VERSION 5.7 ;
BUSBITCHARS "[]" ;
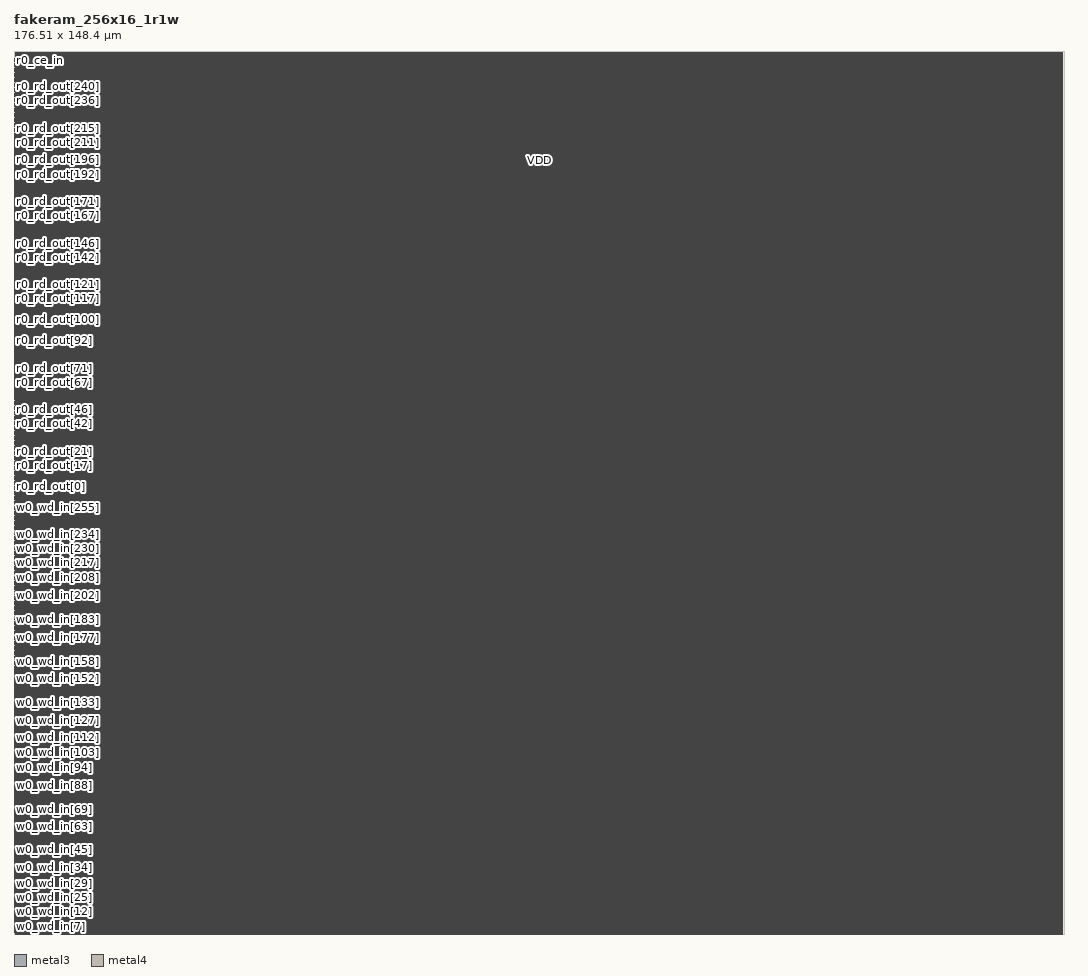
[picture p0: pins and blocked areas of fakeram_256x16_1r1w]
MACRO fakeram_256x16_1r1w
  FOREIGN fakeram_256x16_1r1w 0 0 ;
  SYMMETRY X Y R90 ;
  SIZE 176.510 BY 148.400 ;
  CLASS BLOCK ;
  PIN w0_wd_in[0]
    DIRECTION INPUT ;
    USE SIGNAL ;
    SHAPE ABUTMENT ;
    PORT
      LAYER metal3 ;
      RECT 0.000 0.280 0.140 0.420 ;
    END
  END w0_wd_in[0]
  PIN w0_wd_in[1]
    DIRECTION INPUT ;
    USE SIGNAL ;
    SHAPE ABUTMENT ;
    PORT
      LAYER metal3 ;
      RECT 0.000 0.560 0.140 0.700 ;
    END
  END w0_wd_in[1]
  PIN w0_wd_in[2]
    DIRECTION INPUT ;
    USE SIGNAL ;
    SHAPE ABUTMENT ;
    PORT
      LAYER metal3 ;
      RECT 0.000 0.840 0.140 0.980 ;
    END
  END w0_wd_in[2]
  PIN w0_wd_in[3]
    DIRECTION INPUT ;
    USE SIGNAL ;
    SHAPE ABUTMENT ;
    PORT
      LAYER metal3 ;
      RECT 0.000 1.120 0.140 1.260 ;
    END
  END w0_wd_in[3]
  PIN w0_wd_in[4]
    DIRECTION INPUT ;
    USE SIGNAL ;
    SHAPE ABUTMENT ;
    PORT
      LAYER metal3 ;
      RECT 0.000 1.400 0.140 1.540 ;
    END
  END w0_wd_in[4]
  PIN w0_wd_in[5]
    DIRECTION INPUT ;
    USE SIGNAL ;
    SHAPE ABUTMENT ;
    PORT
      LAYER metal3 ;
      RECT 0.000 1.680 0.140 1.820 ;
    END
  END w0_wd_in[5]
  PIN w0_wd_in[6]
    DIRECTION INPUT ;
    USE SIGNAL ;
    SHAPE ABUTMENT ;
    PORT
      LAYER metal3 ;
      RECT 0.000 1.960 0.140 2.100 ;
    END
  END w0_wd_in[6]
  PIN w0_wd_in[7]
    DIRECTION INPUT ;
    USE SIGNAL ;
    SHAPE ABUTMENT ;
    PORT
      LAYER metal3 ;
      RECT 0.000 2.240 0.140 2.380 ;
    END
  END w0_wd_in[7]
  PIN w0_wd_in[8]
    DIRECTION INPUT ;
    USE SIGNAL ;
    SHAPE ABUTMENT ;
    PORT
      LAYER metal3 ;
      RECT 0.000 2.520 0.140 2.660 ;
    END
  END w0_wd_in[8]
  PIN w0_wd_in[9]
    DIRECTION INPUT ;
    USE SIGNAL ;
    SHAPE ABUTMENT ;
    PORT
      LAYER metal3 ;
      RECT 0.000 2.800 0.140 2.940 ;
    END
  END w0_wd_in[9]
  PIN w0_wd_in[10]
    DIRECTION INPUT ;
    USE SIGNAL ;
    SHAPE ABUTMENT ;
    PORT
      LAYER metal3 ;
      RECT 0.000 3.080 0.140 3.220 ;
    END
  END w0_wd_in[10]
  PIN w0_wd_in[11]
    DIRECTION INPUT ;
    USE SIGNAL ;
    SHAPE ABUTMENT ;
    PORT
      LAYER metal3 ;
      RECT 0.000 3.360 0.140 3.500 ;
    END
  END w0_wd_in[11]
  PIN w0_wd_in[12]
    DIRECTION INPUT ;
    USE SIGNAL ;
    SHAPE ABUTMENT ;
    PORT
      LAYER metal3 ;
      RECT 0.000 3.640 0.140 3.780 ;
    END
  END w0_wd_in[12]
  PIN w0_wd_in[13]
    DIRECTION INPUT ;
    USE SIGNAL ;
    SHAPE ABUTMENT ;
    PORT
      LAYER metal3 ;
      RECT 0.000 3.920 0.140 4.060 ;
    END
  END w0_wd_in[13]
  PIN w0_wd_in[14]
    DIRECTION INPUT ;
    USE SIGNAL ;
    SHAPE ABUTMENT ;
    PORT
      LAYER metal3 ;
      RECT 0.000 4.200 0.140 4.340 ;
    END
  END w0_wd_in[14]
  PIN w0_wd_in[15]
    DIRECTION INPUT ;
    USE SIGNAL ;
    SHAPE ABUTMENT ;
    PORT
      LAYER metal3 ;
      RECT 0.000 4.480 0.140 4.620 ;
    END
  END w0_wd_in[15]
  PIN w0_wd_in[16]
    DIRECTION INPUT ;
    USE SIGNAL ;
    SHAPE ABUTMENT ;
    PORT
      LAYER metal3 ;
      RECT 0.000 4.760 0.140 4.900 ;
    END
  END w0_wd_in[16]
  PIN w0_wd_in[17]
    DIRECTION INPUT ;
    USE SIGNAL ;
    SHAPE ABUTMENT ;
    PORT
      LAYER metal3 ;
      RECT 0.000 5.040 0.140 5.180 ;
    END
  END w0_wd_in[17]
  PIN w0_wd_in[18]
    DIRECTION INPUT ;
    USE SIGNAL ;
    SHAPE ABUTMENT ;
    PORT
      LAYER metal3 ;
      RECT 0.000 5.320 0.140 5.460 ;
    END
  END w0_wd_in[18]
  PIN w0_wd_in[19]
    DIRECTION INPUT ;
    USE SIGNAL ;
    SHAPE ABUTMENT ;
    PORT
      LAYER metal3 ;
      RECT 0.000 5.600 0.140 5.740 ;
    END
  END w0_wd_in[19]
  PIN w0_wd_in[20]
    DIRECTION INPUT ;
    USE SIGNAL ;
    SHAPE ABUTMENT ;
    PORT
      LAYER metal3 ;
      RECT 0.000 5.880 0.140 6.020 ;
    END
  END w0_wd_in[20]
  PIN w0_wd_in[21]
    DIRECTION INPUT ;
    USE SIGNAL ;
    SHAPE ABUTMENT ;
    PORT
      LAYER metal3 ;
      RECT 0.000 6.160 0.140 6.300 ;
    END
  END w0_wd_in[21]
  PIN w0_wd_in[22]
    DIRECTION INPUT ;
    USE SIGNAL ;
    SHAPE ABUTMENT ;
    PORT
      LAYER metal3 ;
      RECT 0.000 6.440 0.140 6.580 ;
    END
  END w0_wd_in[22]
  PIN w0_wd_in[23]
    DIRECTION INPUT ;
    USE SIGNAL ;
    SHAPE ABUTMENT ;
    PORT
      LAYER metal3 ;
      RECT 0.000 6.720 0.140 6.860 ;
    END
  END w0_wd_in[23]
  PIN w0_wd_in[24]
    DIRECTION INPUT ;
    USE SIGNAL ;
    SHAPE ABUTMENT ;
    PORT
      LAYER metal3 ;
      RECT 0.000 7.000 0.140 7.140 ;
    END
  END w0_wd_in[24]
  PIN w0_wd_in[25]
    DIRECTION INPUT ;
    USE SIGNAL ;
    SHAPE ABUTMENT ;
    PORT
      LAYER metal3 ;
      RECT 0.000 7.280 0.140 7.420 ;
    END
  END w0_wd_in[25]
  PIN w0_wd_in[26]
    DIRECTION INPUT ;
    USE SIGNAL ;
    SHAPE ABUTMENT ;
    PORT
      LAYER metal3 ;
      RECT 0.000 7.560 0.140 7.700 ;
    END
  END w0_wd_in[26]
  PIN w0_wd_in[27]
    DIRECTION INPUT ;
    USE SIGNAL ;
    SHAPE ABUTMENT ;
    PORT
      LAYER metal3 ;
      RECT 0.000 7.840 0.140 7.980 ;
    END
  END w0_wd_in[27]
  PIN w0_wd_in[28]
    DIRECTION INPUT ;
    USE SIGNAL ;
    SHAPE ABUTMENT ;
    PORT
      LAYER metal3 ;
      RECT 0.000 8.120 0.140 8.260 ;
    END
  END w0_wd_in[28]
  PIN w0_wd_in[29]
    DIRECTION INPUT ;
    USE SIGNAL ;
    SHAPE ABUTMENT ;
    PORT
      LAYER metal3 ;
      RECT 0.000 8.400 0.140 8.540 ;
    END
  END w0_wd_in[29]
  PIN w0_wd_in[30]
    DIRECTION INPUT ;
    USE SIGNAL ;
    SHAPE ABUTMENT ;
    PORT
      LAYER metal3 ;
      RECT 0.000 8.680 0.140 8.820 ;
    END
  END w0_wd_in[30]
  PIN w0_wd_in[31]
    DIRECTION INPUT ;
    USE SIGNAL ;
    SHAPE ABUTMENT ;
    PORT
      LAYER metal3 ;
      RECT 0.000 8.960 0.140 9.100 ;
    END
  END w0_wd_in[31]
  PIN w0_wd_in[32]
    DIRECTION INPUT ;
    USE SIGNAL ;
    SHAPE ABUTMENT ;
    PORT
      LAYER metal3 ;
      RECT 0.000 9.240 0.140 9.380 ;
    END
  END w0_wd_in[32]
  PIN w0_wd_in[33]
    DIRECTION INPUT ;
    USE SIGNAL ;
    SHAPE ABUTMENT ;
    PORT
      LAYER metal3 ;
      RECT 0.000 9.520 0.140 9.660 ;
    END
  END w0_wd_in[33]
  PIN w0_wd_in[34]
    DIRECTION INPUT ;
    USE SIGNAL ;
    SHAPE ABUTMENT ;
    PORT
      LAYER metal3 ;
      RECT 0.000 9.800 0.140 9.940 ;
    END
  END w0_wd_in[34]
  PIN w0_wd_in[35]
    DIRECTION INPUT ;
    USE SIGNAL ;
    SHAPE ABUTMENT ;
    PORT
      LAYER metal3 ;
      RECT 0.000 10.080 0.140 10.220 ;
    END
  END w0_wd_in[35]
  PIN w0_wd_in[36]
    DIRECTION INPUT ;
    USE SIGNAL ;
    SHAPE ABUTMENT ;
    PORT
      LAYER metal3 ;
      RECT 0.000 10.360 0.140 10.500 ;
    END
  END w0_wd_in[36]
  PIN w0_wd_in[37]
    DIRECTION INPUT ;
    USE SIGNAL ;
    SHAPE ABUTMENT ;
    PORT
      LAYER metal3 ;
      RECT 0.000 10.640 0.140 10.780 ;
    END
  END w0_wd_in[37]
  PIN w0_wd_in[38]
    DIRECTION INPUT ;
    USE SIGNAL ;
    SHAPE ABUTMENT ;
    PORT
      LAYER metal3 ;
      RECT 0.000 10.920 0.140 11.060 ;
    END
  END w0_wd_in[38]
  PIN w0_wd_in[39]
    DIRECTION INPUT ;
    USE SIGNAL ;
    SHAPE ABUTMENT ;
    PORT
      LAYER metal3 ;
      RECT 0.000 11.200 0.140 11.340 ;
    END
  END w0_wd_in[39]
  PIN w0_wd_in[40]
    DIRECTION INPUT ;
    USE SIGNAL ;
    SHAPE ABUTMENT ;
    PORT
      LAYER metal3 ;
      RECT 0.000 11.480 0.140 11.620 ;
    END
  END w0_wd_in[40]
  PIN w0_wd_in[41]
    DIRECTION INPUT ;
    USE SIGNAL ;
    SHAPE ABUTMENT ;
    PORT
      LAYER metal3 ;
      RECT 0.000 11.760 0.140 11.900 ;
    END
  END w0_wd_in[41]
  PIN w0_wd_in[42]
    DIRECTION INPUT ;
    USE SIGNAL ;
    SHAPE ABUTMENT ;
    PORT
      LAYER metal3 ;
      RECT 0.000 12.040 0.140 12.180 ;
    END
  END w0_wd_in[42]
  PIN w0_wd_in[43]
    DIRECTION INPUT ;
    USE SIGNAL ;
    SHAPE ABUTMENT ;
    PORT
      LAYER metal3 ;
      RECT 0.000 12.320 0.140 12.460 ;
    END
  END w0_wd_in[43]
  PIN w0_wd_in[44]
    DIRECTION INPUT ;
    USE SIGNAL ;
    SHAPE ABUTMENT ;
    PORT
      LAYER metal3 ;
      RECT 0.000 12.600 0.140 12.740 ;
    END
  END w0_wd_in[44]
  PIN w0_wd_in[45]
    DIRECTION INPUT ;
    USE SIGNAL ;
    SHAPE ABUTMENT ;
    PORT
      LAYER metal3 ;
      RECT 0.000 12.880 0.140 13.020 ;
    END
  END w0_wd_in[45]
  PIN w0_wd_in[46]
    DIRECTION INPUT ;
    USE SIGNAL ;
    SHAPE ABUTMENT ;
    PORT
      LAYER metal3 ;
      RECT 0.000 13.160 0.140 13.300 ;
    END
  END w0_wd_in[46]
  PIN w0_wd_in[47]
    DIRECTION INPUT ;
    USE SIGNAL ;
    SHAPE ABUTMENT ;
    PORT
      LAYER metal3 ;
      RECT 0.000 13.440 0.140 13.580 ;
    END
  END w0_wd_in[47]
  PIN w0_wd_in[48]
    DIRECTION INPUT ;
    USE SIGNAL ;
    SHAPE ABUTMENT ;
    PORT
      LAYER metal3 ;
      RECT 0.000 13.720 0.140 13.860 ;
    END
  END w0_wd_in[48]
  PIN w0_wd_in[49]
    DIRECTION INPUT ;
    USE SIGNAL ;
    SHAPE ABUTMENT ;
    PORT
      LAYER metal3 ;
      RECT 0.000 14.000 0.140 14.140 ;
    END
  END w0_wd_in[49]
  PIN w0_wd_in[50]
    DIRECTION INPUT ;
    USE SIGNAL ;
    SHAPE ABUTMENT ;
    PORT
      LAYER metal3 ;
      RECT 0.000 14.280 0.140 14.420 ;
    END
  END w0_wd_in[50]
  PIN w0_wd_in[51]
    DIRECTION INPUT ;
    USE SIGNAL ;
    SHAPE ABUTMENT ;
    PORT
      LAYER metal3 ;
      RECT 0.000 14.560 0.140 14.700 ;
    END
  END w0_wd_in[51]
  PIN w0_wd_in[52]
    DIRECTION INPUT ;
    USE SIGNAL ;
    SHAPE ABUTMENT ;
    PORT
      LAYER metal3 ;
      RECT 0.000 14.840 0.140 14.980 ;
    END
  END w0_wd_in[52]
  PIN w0_wd_in[53]
    DIRECTION INPUT ;
    USE SIGNAL ;
    SHAPE ABUTMENT ;
    PORT
      LAYER metal3 ;
      RECT 0.000 15.120 0.140 15.260 ;
    END
  END w0_wd_in[53]
  PIN w0_wd_in[54]
    DIRECTION INPUT ;
    USE SIGNAL ;
    SHAPE ABUTMENT ;
    PORT
      LAYER metal3 ;
      RECT 0.000 15.400 0.140 15.540 ;
    END
  END w0_wd_in[54]
  PIN w0_wd_in[55]
    DIRECTION INPUT ;
    USE SIGNAL ;
    SHAPE ABUTMENT ;
    PORT
      LAYER metal3 ;
      RECT 0.000 15.680 0.140 15.820 ;
    END
  END w0_wd_in[55]
  PIN w0_wd_in[56]
    DIRECTION INPUT ;
    USE SIGNAL ;
    SHAPE ABUTMENT ;
    PORT
      LAYER metal3 ;
      RECT 0.000 15.960 0.140 16.100 ;
    END
  END w0_wd_in[56]
  PIN w0_wd_in[57]
    DIRECTION INPUT ;
    USE SIGNAL ;
    SHAPE ABUTMENT ;
    PORT
      LAYER metal3 ;
      RECT 0.000 16.240 0.140 16.380 ;
    END
  END w0_wd_in[57]
  PIN w0_wd_in[58]
    DIRECTION INPUT ;
    USE SIGNAL ;
    SHAPE ABUTMENT ;
    PORT
      LAYER metal3 ;
      RECT 0.000 16.520 0.140 16.660 ;
    END
  END w0_wd_in[58]
  PIN w0_wd_in[59]
    DIRECTION INPUT ;
    USE SIGNAL ;
    SHAPE ABUTMENT ;
    PORT
      LAYER metal3 ;
      RECT 0.000 16.800 0.140 16.940 ;
    END
  END w0_wd_in[59]
  PIN w0_wd_in[60]
    DIRECTION INPUT ;
    USE SIGNAL ;
    SHAPE ABUTMENT ;
    PORT
      LAYER metal3 ;
      RECT 0.000 17.080 0.140 17.220 ;
    END
  END w0_wd_in[60]
  PIN w0_wd_in[61]
    DIRECTION INPUT ;
    USE SIGNAL ;
    SHAPE ABUTMENT ;
    PORT
      LAYER metal3 ;
      RECT 0.000 17.360 0.140 17.500 ;
    END
  END w0_wd_in[61]
  PIN w0_wd_in[62]
    DIRECTION INPUT ;
    USE SIGNAL ;
    SHAPE ABUTMENT ;
    PORT
      LAYER metal3 ;
      RECT 0.000 17.640 0.140 17.780 ;
    END
  END w0_wd_in[62]
  PIN w0_wd_in[63]
    DIRECTION INPUT ;
    USE SIGNAL ;
    SHAPE ABUTMENT ;
    PORT
      LAYER metal3 ;
      RECT 0.000 17.920 0.140 18.060 ;
    END
  END w0_wd_in[63]
  PIN w0_wd_in[64]
    DIRECTION INPUT ;
    USE SIGNAL ;
    SHAPE ABUTMENT ;
    PORT
      LAYER metal3 ;
      RECT 0.000 18.200 0.140 18.340 ;
    END
  END w0_wd_in[64]
  PIN w0_wd_in[65]
    DIRECTION INPUT ;
    USE SIGNAL ;
    SHAPE ABUTMENT ;
    PORT
      LAYER metal3 ;
      RECT 0.000 18.480 0.140 18.620 ;
    END
  END w0_wd_in[65]
  PIN w0_wd_in[66]
    DIRECTION INPUT ;
    USE SIGNAL ;
    SHAPE ABUTMENT ;
    PORT
      LAYER metal3 ;
      RECT 0.000 18.760 0.140 18.900 ;
    END
  END w0_wd_in[66]
  PIN w0_wd_in[67]
    DIRECTION INPUT ;
    USE SIGNAL ;
    SHAPE ABUTMENT ;
    PORT
      LAYER metal3 ;
      RECT 0.000 19.040 0.140 19.180 ;
    END
  END w0_wd_in[67]
  PIN w0_wd_in[68]
    DIRECTION INPUT ;
    USE SIGNAL ;
    SHAPE ABUTMENT ;
    PORT
      LAYER metal3 ;
      RECT 0.000 19.320 0.140 19.460 ;
    END
  END w0_wd_in[68]
  PIN w0_wd_in[69]
    DIRECTION INPUT ;
    USE SIGNAL ;
    SHAPE ABUTMENT ;
    PORT
      LAYER metal3 ;
      RECT 0.000 19.600 0.140 19.740 ;
    END
  END w0_wd_in[69]
  PIN w0_wd_in[70]
    DIRECTION INPUT ;
    USE SIGNAL ;
    SHAPE ABUTMENT ;
    PORT
      LAYER metal3 ;
      RECT 0.000 19.880 0.140 20.020 ;
    END
  END w0_wd_in[70]
  PIN w0_wd_in[71]
    DIRECTION INPUT ;
    USE SIGNAL ;
    SHAPE ABUTMENT ;
    PORT
      LAYER metal3 ;
      RECT 0.000 20.160 0.140 20.300 ;
    END
  END w0_wd_in[71]
  PIN w0_wd_in[72]
    DIRECTION INPUT ;
    USE SIGNAL ;
    SHAPE ABUTMENT ;
    PORT
      LAYER metal3 ;
      RECT 0.000 20.440 0.140 20.580 ;
    END
  END w0_wd_in[72]
  PIN w0_wd_in[73]
    DIRECTION INPUT ;
    USE SIGNAL ;
    SHAPE ABUTMENT ;
    PORT
      LAYER metal3 ;
      RECT 0.000 20.720 0.140 20.860 ;
    END
  END w0_wd_in[73]
  PIN w0_wd_in[74]
    DIRECTION INPUT ;
    USE SIGNAL ;
    SHAPE ABUTMENT ;
    PORT
      LAYER metal3 ;
      RECT 0.000 21.000 0.140 21.140 ;
    END
  END w0_wd_in[74]
  PIN w0_wd_in[75]
    DIRECTION INPUT ;
    USE SIGNAL ;
    SHAPE ABUTMENT ;
    PORT
      LAYER metal3 ;
      RECT 0.000 21.280 0.140 21.420 ;
    END
  END w0_wd_in[75]
  PIN w0_wd_in[76]
    DIRECTION INPUT ;
    USE SIGNAL ;
    SHAPE ABUTMENT ;
    PORT
      LAYER metal3 ;
      RECT 0.000 21.560 0.140 21.700 ;
    END
  END w0_wd_in[76]
  PIN w0_wd_in[77]
    DIRECTION INPUT ;
    USE SIGNAL ;
    SHAPE ABUTMENT ;
    PORT
      LAYER metal3 ;
      RECT 0.000 21.840 0.140 21.980 ;
    END
  END w0_wd_in[77]
  PIN w0_wd_in[78]
    DIRECTION INPUT ;
    USE SIGNAL ;
    SHAPE ABUTMENT ;
    PORT
      LAYER metal3 ;
      RECT 0.000 22.120 0.140 22.260 ;
    END
  END w0_wd_in[78]
  PIN w0_wd_in[79]
    DIRECTION INPUT ;
    USE SIGNAL ;
    SHAPE ABUTMENT ;
    PORT
      LAYER metal3 ;
      RECT 0.000 22.400 0.140 22.540 ;
    END
  END w0_wd_in[79]
  PIN w0_wd_in[80]
    DIRECTION INPUT ;
    USE SIGNAL ;
    SHAPE ABUTMENT ;
    PORT
      LAYER metal3 ;
      RECT 0.000 22.680 0.140 22.820 ;
    END
  END w0_wd_in[80]
  PIN w0_wd_in[81]
    DIRECTION INPUT ;
    USE SIGNAL ;
    SHAPE ABUTMENT ;
    PORT
      LAYER metal3 ;
      RECT 0.000 22.960 0.140 23.100 ;
    END
  END w0_wd_in[81]
  PIN w0_wd_in[82]
    DIRECTION INPUT ;
    USE SIGNAL ;
    SHAPE ABUTMENT ;
    PORT
      LAYER metal3 ;
      RECT 0.000 23.240 0.140 23.380 ;
    END
  END w0_wd_in[82]
  PIN w0_wd_in[83]
    DIRECTION INPUT ;
    USE SIGNAL ;
    SHAPE ABUTMENT ;
    PORT
      LAYER metal3 ;
      RECT 0.000 23.520 0.140 23.660 ;
    END
  END w0_wd_in[83]
  PIN w0_wd_in[84]
    DIRECTION INPUT ;
    USE SIGNAL ;
    SHAPE ABUTMENT ;
    PORT
      LAYER metal3 ;
      RECT 0.000 23.800 0.140 23.940 ;
    END
  END w0_wd_in[84]
  PIN w0_wd_in[85]
    DIRECTION INPUT ;
    USE SIGNAL ;
    SHAPE ABUTMENT ;
    PORT
      LAYER metal3 ;
      RECT 0.000 24.080 0.140 24.220 ;
    END
  END w0_wd_in[85]
  PIN w0_wd_in[86]
    DIRECTION INPUT ;
    USE SIGNAL ;
    SHAPE ABUTMENT ;
    PORT
      LAYER metal3 ;
      RECT 0.000 24.360 0.140 24.500 ;
    END
  END w0_wd_in[86]
  PIN w0_wd_in[87]
    DIRECTION INPUT ;
    USE SIGNAL ;
    SHAPE ABUTMENT ;
    PORT
      LAYER metal3 ;
      RECT 0.000 24.640 0.140 24.780 ;
    END
  END w0_wd_in[87]
  PIN w0_wd_in[88]
    DIRECTION INPUT ;
    USE SIGNAL ;
    SHAPE ABUTMENT ;
    PORT
      LAYER metal3 ;
      RECT 0.000 24.920 0.140 25.060 ;
    END
  END w0_wd_in[88]
  PIN w0_wd_in[89]
    DIRECTION INPUT ;
    USE SIGNAL ;
    SHAPE ABUTMENT ;
    PORT
      LAYER metal3 ;
      RECT 0.000 25.200 0.140 25.340 ;
    END
  END w0_wd_in[89]
  PIN w0_wd_in[90]
    DIRECTION INPUT ;
    USE SIGNAL ;
    SHAPE ABUTMENT ;
    PORT
      LAYER metal3 ;
      RECT 0.000 25.480 0.140 25.620 ;
    END
  END w0_wd_in[90]
  PIN w0_wd_in[91]
    DIRECTION INPUT ;
    USE SIGNAL ;
    SHAPE ABUTMENT ;
    PORT
      LAYER metal3 ;
      RECT 0.000 25.760 0.140 25.900 ;
    END
  END w0_wd_in[91]
  PIN w0_wd_in[92]
    DIRECTION INPUT ;
    USE SIGNAL ;
    SHAPE ABUTMENT ;
    PORT
      LAYER metal3 ;
      RECT 0.000 26.040 0.140 26.180 ;
    END
  END w0_wd_in[92]
  PIN w0_wd_in[93]
    DIRECTION INPUT ;
    USE SIGNAL ;
    SHAPE ABUTMENT ;
    PORT
      LAYER metal3 ;
      RECT 0.000 26.320 0.140 26.460 ;
    END
  END w0_wd_in[93]
  PIN w0_wd_in[94]
    DIRECTION INPUT ;
    USE SIGNAL ;
    SHAPE ABUTMENT ;
    PORT
      LAYER metal3 ;
      RECT 0.000 26.600 0.140 26.740 ;
    END
  END w0_wd_in[94]
  PIN w0_wd_in[95]
    DIRECTION INPUT ;
    USE SIGNAL ;
    SHAPE ABUTMENT ;
    PORT
      LAYER metal3 ;
      RECT 0.000 26.880 0.140 27.020 ;
    END
  END w0_wd_in[95]
  PIN w0_wd_in[96]
    DIRECTION INPUT ;
    USE SIGNAL ;
    SHAPE ABUTMENT ;
    PORT
      LAYER metal3 ;
      RECT 0.000 27.160 0.140 27.300 ;
    END
  END w0_wd_in[96]
  PIN w0_wd_in[97]
    DIRECTION INPUT ;
    USE SIGNAL ;
    SHAPE ABUTMENT ;
    PORT
      LAYER metal3 ;
      RECT 0.000 27.440 0.140 27.580 ;
    END
  END w0_wd_in[97]
  PIN w0_wd_in[98]
    DIRECTION INPUT ;
    USE SIGNAL ;
    SHAPE ABUTMENT ;
    PORT
      LAYER metal3 ;
      RECT 0.000 27.720 0.140 27.860 ;
    END
  END w0_wd_in[98]
  PIN w0_wd_in[99]
    DIRECTION INPUT ;
    USE SIGNAL ;
    SHAPE ABUTMENT ;
    PORT
      LAYER metal3 ;
      RECT 0.000 28.000 0.140 28.140 ;
    END
  END w0_wd_in[99]
  PIN w0_wd_in[100]
    DIRECTION INPUT ;
    USE SIGNAL ;
    SHAPE ABUTMENT ;
    PORT
      LAYER metal3 ;
      RECT 0.000 28.280 0.140 28.420 ;
    END
  END w0_wd_in[100]
  PIN w0_wd_in[101]
    DIRECTION INPUT ;
    USE SIGNAL ;
    SHAPE ABUTMENT ;
    PORT
      LAYER metal3 ;
      RECT 0.000 28.560 0.140 28.700 ;
    END
  END w0_wd_in[101]
  PIN w0_wd_in[102]
    DIRECTION INPUT ;
    USE SIGNAL ;
    SHAPE ABUTMENT ;
    PORT
      LAYER metal3 ;
      RECT 0.000 28.840 0.140 28.980 ;
    END
  END w0_wd_in[102]
  PIN w0_wd_in[103]
    DIRECTION INPUT ;
    USE SIGNAL ;
    SHAPE ABUTMENT ;
    PORT
      LAYER metal3 ;
      RECT 0.000 29.120 0.140 29.260 ;
    END
  END w0_wd_in[103]
  PIN w0_wd_in[104]
    DIRECTION INPUT ;
    USE SIGNAL ;
    SHAPE ABUTMENT ;
    PORT
      LAYER metal3 ;
      RECT 0.000 29.400 0.140 29.540 ;
    END
  END w0_wd_in[104]
  PIN w0_wd_in[105]
    DIRECTION INPUT ;
    USE SIGNAL ;
    SHAPE ABUTMENT ;
    PORT
      LAYER metal3 ;
      RECT 0.000 29.680 0.140 29.820 ;
    END
  END w0_wd_in[105]
  PIN w0_wd_in[106]
    DIRECTION INPUT ;
    USE SIGNAL ;
    SHAPE ABUTMENT ;
    PORT
      LAYER metal3 ;
      RECT 0.000 29.960 0.140 30.100 ;
    END
  END w0_wd_in[106]
  PIN w0_wd_in[107]
    DIRECTION INPUT ;
    USE SIGNAL ;
    SHAPE ABUTMENT ;
    PORT
      LAYER metal3 ;
      RECT 0.000 30.240 0.140 30.380 ;
    END
  END w0_wd_in[107]
  PIN w0_wd_in[108]
    DIRECTION INPUT ;
    USE SIGNAL ;
    SHAPE ABUTMENT ;
    PORT
      LAYER metal3 ;
      RECT 0.000 30.520 0.140 30.660 ;
    END
  END w0_wd_in[108]
  PIN w0_wd_in[109]
    DIRECTION INPUT ;
    USE SIGNAL ;
    SHAPE ABUTMENT ;
    PORT
      LAYER metal3 ;
      RECT 0.000 30.800 0.140 30.940 ;
    END
  END w0_wd_in[109]
  PIN w0_wd_in[110]
    DIRECTION INPUT ;
    USE SIGNAL ;
    SHAPE ABUTMENT ;
    PORT
      LAYER metal3 ;
      RECT 0.000 31.080 0.140 31.220 ;
    END
  END w0_wd_in[110]
  PIN w0_wd_in[111]
    DIRECTION INPUT ;
    USE SIGNAL ;
    SHAPE ABUTMENT ;
    PORT
      LAYER metal3 ;
      RECT 0.000 31.360 0.140 31.500 ;
    END
  END w0_wd_in[111]
  PIN w0_wd_in[112]
    DIRECTION INPUT ;
    USE SIGNAL ;
    SHAPE ABUTMENT ;
    PORT
      LAYER metal3 ;
      RECT 0.000 31.640 0.140 31.780 ;
    END
  END w0_wd_in[112]
  PIN w0_wd_in[113]
    DIRECTION INPUT ;
    USE SIGNAL ;
    SHAPE ABUTMENT ;
    PORT
      LAYER metal3 ;
      RECT 0.000 31.920 0.140 32.060 ;
    END
  END w0_wd_in[113]
  PIN w0_wd_in[114]
    DIRECTION INPUT ;
    USE SIGNAL ;
    SHAPE ABUTMENT ;
    PORT
      LAYER metal3 ;
      RECT 0.000 32.200 0.140 32.340 ;
    END
  END w0_wd_in[114]
  PIN w0_wd_in[115]
    DIRECTION INPUT ;
    USE SIGNAL ;
    SHAPE ABUTMENT ;
    PORT
      LAYER metal3 ;
      RECT 0.000 32.480 0.140 32.620 ;
    END
  END w0_wd_in[115]
  PIN w0_wd_in[116]
    DIRECTION INPUT ;
    USE SIGNAL ;
    SHAPE ABUTMENT ;
    PORT
      LAYER metal3 ;
      RECT 0.000 32.760 0.140 32.900 ;
    END
  END w0_wd_in[116]
  PIN w0_wd_in[117]
    DIRECTION INPUT ;
    USE SIGNAL ;
    SHAPE ABUTMENT ;
    PORT
      LAYER metal3 ;
      RECT 0.000 33.040 0.140 33.180 ;
    END
  END w0_wd_in[117]
  PIN w0_wd_in[118]
    DIRECTION INPUT ;
    USE SIGNAL ;
    SHAPE ABUTMENT ;
    PORT
      LAYER metal3 ;
      RECT 0.000 33.320 0.140 33.460 ;
    END
  END w0_wd_in[118]
  PIN w0_wd_in[119]
    DIRECTION INPUT ;
    USE SIGNAL ;
    SHAPE ABUTMENT ;
    PORT
      LAYER metal3 ;
      RECT 0.000 33.600 0.140 33.740 ;
    END
  END w0_wd_in[119]
  PIN w0_wd_in[120]
    DIRECTION INPUT ;
    USE SIGNAL ;
    SHAPE ABUTMENT ;
    PORT
      LAYER metal3 ;
      RECT 0.000 33.880 0.140 34.020 ;
    END
  END w0_wd_in[120]
  PIN w0_wd_in[121]
    DIRECTION INPUT ;
    USE SIGNAL ;
    SHAPE ABUTMENT ;
    PORT
      LAYER metal3 ;
      RECT 0.000 34.160 0.140 34.300 ;
    END
  END w0_wd_in[121]
  PIN w0_wd_in[122]
    DIRECTION INPUT ;
    USE SIGNAL ;
    SHAPE ABUTMENT ;
    PORT
      LAYER metal3 ;
      RECT 0.000 34.440 0.140 34.580 ;
    END
  END w0_wd_in[122]
  PIN w0_wd_in[123]
    DIRECTION INPUT ;
    USE SIGNAL ;
    SHAPE ABUTMENT ;
    PORT
      LAYER metal3 ;
      RECT 0.000 34.720 0.140 34.860 ;
    END
  END w0_wd_in[123]
  PIN w0_wd_in[124]
    DIRECTION INPUT ;
    USE SIGNAL ;
    SHAPE ABUTMENT ;
    PORT
      LAYER metal3 ;
      RECT 0.000 35.000 0.140 35.140 ;
    END
  END w0_wd_in[124]
  PIN w0_wd_in[125]
    DIRECTION INPUT ;
    USE SIGNAL ;
    SHAPE ABUTMENT ;
    PORT
      LAYER metal3 ;
      RECT 0.000 35.280 0.140 35.420 ;
    END
  END w0_wd_in[125]
  PIN w0_wd_in[126]
    DIRECTION INPUT ;
    USE SIGNAL ;
    SHAPE ABUTMENT ;
    PORT
      LAYER metal3 ;
      RECT 0.000 35.560 0.140 35.700 ;
    END
  END w0_wd_in[126]
  PIN w0_wd_in[127]
    DIRECTION INPUT ;
    USE SIGNAL ;
    SHAPE ABUTMENT ;
    PORT
      LAYER metal3 ;
      RECT 0.000 35.840 0.140 35.980 ;
    END
  END w0_wd_in[127]
  PIN w0_wd_in[128]
    DIRECTION INPUT ;
    USE SIGNAL ;
    SHAPE ABUTMENT ;
    PORT
      LAYER metal3 ;
      RECT 0.000 36.120 0.140 36.260 ;
    END
  END w0_wd_in[128]
  PIN w0_wd_in[129]
    DIRECTION INPUT ;
    USE SIGNAL ;
    SHAPE ABUTMENT ;
    PORT
      LAYER metal3 ;
      RECT 0.000 36.400 0.140 36.540 ;
    END
  END w0_wd_in[129]
  PIN w0_wd_in[130]
    DIRECTION INPUT ;
    USE SIGNAL ;
    SHAPE ABUTMENT ;
    PORT
      LAYER metal3 ;
      RECT 0.000 36.680 0.140 36.820 ;
    END
  END w0_wd_in[130]
  PIN w0_wd_in[131]
    DIRECTION INPUT ;
    USE SIGNAL ;
    SHAPE ABUTMENT ;
    PORT
      LAYER metal3 ;
      RECT 0.000 36.960 0.140 37.100 ;
    END
  END w0_wd_in[131]
  PIN w0_wd_in[132]
    DIRECTION INPUT ;
    USE SIGNAL ;
    SHAPE ABUTMENT ;
    PORT
      LAYER metal3 ;
      RECT 0.000 37.240 0.140 37.380 ;
    END
  END w0_wd_in[132]
  PIN w0_wd_in[133]
    DIRECTION INPUT ;
    USE SIGNAL ;
    SHAPE ABUTMENT ;
    PORT
      LAYER metal3 ;
      RECT 0.000 37.520 0.140 37.660 ;
    END
  END w0_wd_in[133]
  PIN w0_wd_in[134]
    DIRECTION INPUT ;
    USE SIGNAL ;
    SHAPE ABUTMENT ;
    PORT
      LAYER metal3 ;
      RECT 0.000 37.800 0.140 37.940 ;
    END
  END w0_wd_in[134]
  PIN w0_wd_in[135]
    DIRECTION INPUT ;
    USE SIGNAL ;
    SHAPE ABUTMENT ;
    PORT
      LAYER metal3 ;
      RECT 0.000 38.080 0.140 38.220 ;
    END
  END w0_wd_in[135]
  PIN w0_wd_in[136]
    DIRECTION INPUT ;
    USE SIGNAL ;
    SHAPE ABUTMENT ;
    PORT
      LAYER metal3 ;
      RECT 0.000 38.360 0.140 38.500 ;
    END
  END w0_wd_in[136]
  PIN w0_wd_in[137]
    DIRECTION INPUT ;
    USE SIGNAL ;
    SHAPE ABUTMENT ;
    PORT
      LAYER metal3 ;
      RECT 0.000 38.640 0.140 38.780 ;
    END
  END w0_wd_in[137]
  PIN w0_wd_in[138]
    DIRECTION INPUT ;
    USE SIGNAL ;
    SHAPE ABUTMENT ;
    PORT
      LAYER metal3 ;
      RECT 0.000 38.920 0.140 39.060 ;
    END
  END w0_wd_in[138]
  PIN w0_wd_in[139]
    DIRECTION INPUT ;
    USE SIGNAL ;
    SHAPE ABUTMENT ;
    PORT
      LAYER metal3 ;
      RECT 0.000 39.200 0.140 39.340 ;
    END
  END w0_wd_in[139]
  PIN w0_wd_in[140]
    DIRECTION INPUT ;
    USE SIGNAL ;
    SHAPE ABUTMENT ;
    PORT
      LAYER metal3 ;
      RECT 0.000 39.480 0.140 39.620 ;
    END
  END w0_wd_in[140]
  PIN w0_wd_in[141]
    DIRECTION INPUT ;
    USE SIGNAL ;
    SHAPE ABUTMENT ;
    PORT
      LAYER metal3 ;
      RECT 0.000 39.760 0.140 39.900 ;
    END
  END w0_wd_in[141]
  PIN w0_wd_in[142]
    DIRECTION INPUT ;
    USE SIGNAL ;
    SHAPE ABUTMENT ;
    PORT
      LAYER metal3 ;
      RECT 0.000 40.040 0.140 40.180 ;
    END
  END w0_wd_in[142]
  PIN w0_wd_in[143]
    DIRECTION INPUT ;
    USE SIGNAL ;
    SHAPE ABUTMENT ;
    PORT
      LAYER metal3 ;
      RECT 0.000 40.320 0.140 40.460 ;
    END
  END w0_wd_in[143]
  PIN w0_wd_in[144]
    DIRECTION INPUT ;
    USE SIGNAL ;
    SHAPE ABUTMENT ;
    PORT
      LAYER metal3 ;
      RECT 0.000 40.600 0.140 40.740 ;
    END
  END w0_wd_in[144]
  PIN w0_wd_in[145]
    DIRECTION INPUT ;
    USE SIGNAL ;
    SHAPE ABUTMENT ;
    PORT
      LAYER metal3 ;
      RECT 0.000 40.880 0.140 41.020 ;
    END
  END w0_wd_in[145]
  PIN w0_wd_in[146]
    DIRECTION INPUT ;
    USE SIGNAL ;
    SHAPE ABUTMENT ;
    PORT
      LAYER metal3 ;
      RECT 0.000 41.160 0.140 41.300 ;
    END
  END w0_wd_in[146]
  PIN w0_wd_in[147]
    DIRECTION INPUT ;
    USE SIGNAL ;
    SHAPE ABUTMENT ;
    PORT
      LAYER metal3 ;
      RECT 0.000 41.440 0.140 41.580 ;
    END
  END w0_wd_in[147]
  PIN w0_wd_in[148]
    DIRECTION INPUT ;
    USE SIGNAL ;
    SHAPE ABUTMENT ;
    PORT
      LAYER metal3 ;
      RECT 0.000 41.720 0.140 41.860 ;
    END
  END w0_wd_in[148]
  PIN w0_wd_in[149]
    DIRECTION INPUT ;
    USE SIGNAL ;
    SHAPE ABUTMENT ;
    PORT
      LAYER metal3 ;
      RECT 0.000 42.000 0.140 42.140 ;
    END
  END w0_wd_in[149]
  PIN w0_wd_in[150]
    DIRECTION INPUT ;
    USE SIGNAL ;
    SHAPE ABUTMENT ;
    PORT
      LAYER metal3 ;
      RECT 0.000 42.280 0.140 42.420 ;
    END
  END w0_wd_in[150]
  PIN w0_wd_in[151]
    DIRECTION INPUT ;
    USE SIGNAL ;
    SHAPE ABUTMENT ;
    PORT
      LAYER metal3 ;
      RECT 0.000 42.560 0.140 42.700 ;
    END
  END w0_wd_in[151]
  PIN w0_wd_in[152]
    DIRECTION INPUT ;
    USE SIGNAL ;
    SHAPE ABUTMENT ;
    PORT
      LAYER metal3 ;
      RECT 0.000 42.840 0.140 42.980 ;
    END
  END w0_wd_in[152]
  PIN w0_wd_in[153]
    DIRECTION INPUT ;
    USE SIGNAL ;
    SHAPE ABUTMENT ;
    PORT
      LAYER metal3 ;
      RECT 0.000 43.120 0.140 43.260 ;
    END
  END w0_wd_in[153]
  PIN w0_wd_in[154]
    DIRECTION INPUT ;
    USE SIGNAL ;
    SHAPE ABUTMENT ;
    PORT
      LAYER metal3 ;
      RECT 0.000 43.400 0.140 43.540 ;
    END
  END w0_wd_in[154]
  PIN w0_wd_in[155]
    DIRECTION INPUT ;
    USE SIGNAL ;
    SHAPE ABUTMENT ;
    PORT
      LAYER metal3 ;
      RECT 0.000 43.680 0.140 43.820 ;
    END
  END w0_wd_in[155]
  PIN w0_wd_in[156]
    DIRECTION INPUT ;
    USE SIGNAL ;
    SHAPE ABUTMENT ;
    PORT
      LAYER metal3 ;
      RECT 0.000 43.960 0.140 44.100 ;
    END
  END w0_wd_in[156]
  PIN w0_wd_in[157]
    DIRECTION INPUT ;
    USE SIGNAL ;
    SHAPE ABUTMENT ;
    PORT
      LAYER metal3 ;
      RECT 0.000 44.240 0.140 44.380 ;
    END
  END w0_wd_in[157]
  PIN w0_wd_in[158]
    DIRECTION INPUT ;
    USE SIGNAL ;
    SHAPE ABUTMENT ;
    PORT
      LAYER metal3 ;
      RECT 0.000 44.520 0.140 44.660 ;
    END
  END w0_wd_in[158]
  PIN w0_wd_in[159]
    DIRECTION INPUT ;
    USE SIGNAL ;
    SHAPE ABUTMENT ;
    PORT
      LAYER metal3 ;
      RECT 0.000 44.800 0.140 44.940 ;
    END
  END w0_wd_in[159]
  PIN w0_wd_in[160]
    DIRECTION INPUT ;
    USE SIGNAL ;
    SHAPE ABUTMENT ;
    PORT
      LAYER metal3 ;
      RECT 0.000 45.080 0.140 45.220 ;
    END
  END w0_wd_in[160]
  PIN w0_wd_in[161]
    DIRECTION INPUT ;
    USE SIGNAL ;
    SHAPE ABUTMENT ;
    PORT
      LAYER metal3 ;
      RECT 0.000 45.360 0.140 45.500 ;
    END
  END w0_wd_in[161]
  PIN w0_wd_in[162]
    DIRECTION INPUT ;
    USE SIGNAL ;
    SHAPE ABUTMENT ;
    PORT
      LAYER metal3 ;
      RECT 0.000 45.640 0.140 45.780 ;
    END
  END w0_wd_in[162]
  PIN w0_wd_in[163]
    DIRECTION INPUT ;
    USE SIGNAL ;
    SHAPE ABUTMENT ;
    PORT
      LAYER metal3 ;
      RECT 0.000 45.920 0.140 46.060 ;
    END
  END w0_wd_in[163]
  PIN w0_wd_in[164]
    DIRECTION INPUT ;
    USE SIGNAL ;
    SHAPE ABUTMENT ;
    PORT
      LAYER metal3 ;
      RECT 0.000 46.200 0.140 46.340 ;
    END
  END w0_wd_in[164]
  PIN w0_wd_in[165]
    DIRECTION INPUT ;
    USE SIGNAL ;
    SHAPE ABUTMENT ;
    PORT
      LAYER metal3 ;
      RECT 0.000 46.480 0.140 46.620 ;
    END
  END w0_wd_in[165]
  PIN w0_wd_in[166]
    DIRECTION INPUT ;
    USE SIGNAL ;
    SHAPE ABUTMENT ;
    PORT
      LAYER metal3 ;
      RECT 0.000 46.760 0.140 46.900 ;
    END
  END w0_wd_in[166]
  PIN w0_wd_in[167]
    DIRECTION INPUT ;
    USE SIGNAL ;
    SHAPE ABUTMENT ;
    PORT
      LAYER metal3 ;
      RECT 0.000 47.040 0.140 47.180 ;
    END
  END w0_wd_in[167]
  PIN w0_wd_in[168]
    DIRECTION INPUT ;
    USE SIGNAL ;
    SHAPE ABUTMENT ;
    PORT
      LAYER metal3 ;
      RECT 0.000 47.320 0.140 47.460 ;
    END
  END w0_wd_in[168]
  PIN w0_wd_in[169]
    DIRECTION INPUT ;
    USE SIGNAL ;
    SHAPE ABUTMENT ;
    PORT
      LAYER metal3 ;
      RECT 0.000 47.600 0.140 47.740 ;
    END
  END w0_wd_in[169]
  PIN w0_wd_in[170]
    DIRECTION INPUT ;
    USE SIGNAL ;
    SHAPE ABUTMENT ;
    PORT
      LAYER metal3 ;
      RECT 0.000 47.880 0.140 48.020 ;
    END
  END w0_wd_in[170]
  PIN w0_wd_in[171]
    DIRECTION INPUT ;
    USE SIGNAL ;
    SHAPE ABUTMENT ;
    PORT
      LAYER metal3 ;
      RECT 0.000 48.160 0.140 48.300 ;
    END
  END w0_wd_in[171]
  PIN w0_wd_in[172]
    DIRECTION INPUT ;
    USE SIGNAL ;
    SHAPE ABUTMENT ;
    PORT
      LAYER metal3 ;
      RECT 0.000 48.440 0.140 48.580 ;
    END
  END w0_wd_in[172]
  PIN w0_wd_in[173]
    DIRECTION INPUT ;
    USE SIGNAL ;
    SHAPE ABUTMENT ;
    PORT
      LAYER metal3 ;
      RECT 0.000 48.720 0.140 48.860 ;
    END
  END w0_wd_in[173]
  PIN w0_wd_in[174]
    DIRECTION INPUT ;
    USE SIGNAL ;
    SHAPE ABUTMENT ;
    PORT
      LAYER metal3 ;
      RECT 0.000 49.000 0.140 49.140 ;
    END
  END w0_wd_in[174]
  PIN w0_wd_in[175]
    DIRECTION INPUT ;
    USE SIGNAL ;
    SHAPE ABUTMENT ;
    PORT
      LAYER metal3 ;
      RECT 0.000 49.280 0.140 49.420 ;
    END
  END w0_wd_in[175]
  PIN w0_wd_in[176]
    DIRECTION INPUT ;
    USE SIGNAL ;
    SHAPE ABUTMENT ;
    PORT
      LAYER metal3 ;
      RECT 0.000 49.560 0.140 49.700 ;
    END
  END w0_wd_in[176]
  PIN w0_wd_in[177]
    DIRECTION INPUT ;
    USE SIGNAL ;
    SHAPE ABUTMENT ;
    PORT
      LAYER metal3 ;
      RECT 0.000 49.840 0.140 49.980 ;
    END
  END w0_wd_in[177]
  PIN w0_wd_in[178]
    DIRECTION INPUT ;
    USE SIGNAL ;
    SHAPE ABUTMENT ;
    PORT
      LAYER metal3 ;
      RECT 0.000 50.120 0.140 50.260 ;
    END
  END w0_wd_in[178]
  PIN w0_wd_in[179]
    DIRECTION INPUT ;
    USE SIGNAL ;
    SHAPE ABUTMENT ;
    PORT
      LAYER metal3 ;
      RECT 0.000 50.400 0.140 50.540 ;
    END
  END w0_wd_in[179]
  PIN w0_wd_in[180]
    DIRECTION INPUT ;
    USE SIGNAL ;
    SHAPE ABUTMENT ;
    PORT
      LAYER metal3 ;
      RECT 0.000 50.680 0.140 50.820 ;
    END
  END w0_wd_in[180]
  PIN w0_wd_in[181]
    DIRECTION INPUT ;
    USE SIGNAL ;
    SHAPE ABUTMENT ;
    PORT
      LAYER metal3 ;
      RECT 0.000 50.960 0.140 51.100 ;
    END
  END w0_wd_in[181]
  PIN w0_wd_in[182]
    DIRECTION INPUT ;
    USE SIGNAL ;
    SHAPE ABUTMENT ;
    PORT
      LAYER metal3 ;
      RECT 0.000 51.240 0.140 51.380 ;
    END
  END w0_wd_in[182]
  PIN w0_wd_in[183]
    DIRECTION INPUT ;
    USE SIGNAL ;
    SHAPE ABUTMENT ;
    PORT
      LAYER metal3 ;
      RECT 0.000 51.520 0.140 51.660 ;
    END
  END w0_wd_in[183]
  PIN w0_wd_in[184]
    DIRECTION INPUT ;
    USE SIGNAL ;
    SHAPE ABUTMENT ;
    PORT
      LAYER metal3 ;
      RECT 0.000 51.800 0.140 51.940 ;
    END
  END w0_wd_in[184]
  PIN w0_wd_in[185]
    DIRECTION INPUT ;
    USE SIGNAL ;
    SHAPE ABUTMENT ;
    PORT
      LAYER metal3 ;
      RECT 0.000 52.080 0.140 52.220 ;
    END
  END w0_wd_in[185]
  PIN w0_wd_in[186]
    DIRECTION INPUT ;
    USE SIGNAL ;
    SHAPE ABUTMENT ;
    PORT
      LAYER metal3 ;
      RECT 0.000 52.360 0.140 52.500 ;
    END
  END w0_wd_in[186]
  PIN w0_wd_in[187]
    DIRECTION INPUT ;
    USE SIGNAL ;
    SHAPE ABUTMENT ;
    PORT
      LAYER metal3 ;
      RECT 0.000 52.640 0.140 52.780 ;
    END
  END w0_wd_in[187]
  PIN w0_wd_in[188]
    DIRECTION INPUT ;
    USE SIGNAL ;
    SHAPE ABUTMENT ;
    PORT
      LAYER metal3 ;
      RECT 0.000 52.920 0.140 53.060 ;
    END
  END w0_wd_in[188]
  PIN w0_wd_in[189]
    DIRECTION INPUT ;
    USE SIGNAL ;
    SHAPE ABUTMENT ;
    PORT
      LAYER metal3 ;
      RECT 0.000 53.200 0.140 53.340 ;
    END
  END w0_wd_in[189]
  PIN w0_wd_in[190]
    DIRECTION INPUT ;
    USE SIGNAL ;
    SHAPE ABUTMENT ;
    PORT
      LAYER metal3 ;
      RECT 0.000 53.480 0.140 53.620 ;
    END
  END w0_wd_in[190]
  PIN w0_wd_in[191]
    DIRECTION INPUT ;
    USE SIGNAL ;
    SHAPE ABUTMENT ;
    PORT
      LAYER metal3 ;
      RECT 0.000 53.760 0.140 53.900 ;
    END
  END w0_wd_in[191]
  PIN w0_wd_in[192]
    DIRECTION INPUT ;
    USE SIGNAL ;
    SHAPE ABUTMENT ;
    PORT
      LAYER metal3 ;
      RECT 0.000 54.040 0.140 54.180 ;
    END
  END w0_wd_in[192]
  PIN w0_wd_in[193]
    DIRECTION INPUT ;
    USE SIGNAL ;
    SHAPE ABUTMENT ;
    PORT
      LAYER metal3 ;
      RECT 0.000 54.320 0.140 54.460 ;
    END
  END w0_wd_in[193]
  PIN w0_wd_in[194]
    DIRECTION INPUT ;
    USE SIGNAL ;
    SHAPE ABUTMENT ;
    PORT
      LAYER metal3 ;
      RECT 0.000 54.600 0.140 54.740 ;
    END
  END w0_wd_in[194]
  PIN w0_wd_in[195]
    DIRECTION INPUT ;
    USE SIGNAL ;
    SHAPE ABUTMENT ;
    PORT
      LAYER metal3 ;
      RECT 0.000 54.880 0.140 55.020 ;
    END
  END w0_wd_in[195]
  PIN w0_wd_in[196]
    DIRECTION INPUT ;
    USE SIGNAL ;
    SHAPE ABUTMENT ;
    PORT
      LAYER metal3 ;
      RECT 0.000 55.160 0.140 55.300 ;
    END
  END w0_wd_in[196]
  PIN w0_wd_in[197]
    DIRECTION INPUT ;
    USE SIGNAL ;
    SHAPE ABUTMENT ;
    PORT
      LAYER metal3 ;
      RECT 0.000 55.440 0.140 55.580 ;
    END
  END w0_wd_in[197]
  PIN w0_wd_in[198]
    DIRECTION INPUT ;
    USE SIGNAL ;
    SHAPE ABUTMENT ;
    PORT
      LAYER metal3 ;
      RECT 0.000 55.720 0.140 55.860 ;
    END
  END w0_wd_in[198]
  PIN w0_wd_in[199]
    DIRECTION INPUT ;
    USE SIGNAL ;
    SHAPE ABUTMENT ;
    PORT
      LAYER metal3 ;
      RECT 0.000 56.000 0.140 56.140 ;
    END
  END w0_wd_in[199]
  PIN w0_wd_in[200]
    DIRECTION INPUT ;
    USE SIGNAL ;
    SHAPE ABUTMENT ;
    PORT
      LAYER metal3 ;
      RECT 0.000 56.280 0.140 56.420 ;
    END
  END w0_wd_in[200]
  PIN w0_wd_in[201]
    DIRECTION INPUT ;
    USE SIGNAL ;
    SHAPE ABUTMENT ;
    PORT
      LAYER metal3 ;
      RECT 0.000 56.560 0.140 56.700 ;
    END
  END w0_wd_in[201]
  PIN w0_wd_in[202]
    DIRECTION INPUT ;
    USE SIGNAL ;
    SHAPE ABUTMENT ;
    PORT
      LAYER metal3 ;
      RECT 0.000 56.840 0.140 56.980 ;
    END
  END w0_wd_in[202]
  PIN w0_wd_in[203]
    DIRECTION INPUT ;
    USE SIGNAL ;
    SHAPE ABUTMENT ;
    PORT
      LAYER metal3 ;
      RECT 0.000 57.120 0.140 57.260 ;
    END
  END w0_wd_in[203]
  PIN w0_wd_in[204]
    DIRECTION INPUT ;
    USE SIGNAL ;
    SHAPE ABUTMENT ;
    PORT
      LAYER metal3 ;
      RECT 0.000 57.400 0.140 57.540 ;
    END
  END w0_wd_in[204]
  PIN w0_wd_in[205]
    DIRECTION INPUT ;
    USE SIGNAL ;
    SHAPE ABUTMENT ;
    PORT
      LAYER metal3 ;
      RECT 0.000 57.680 0.140 57.820 ;
    END
  END w0_wd_in[205]
  PIN w0_wd_in[206]
    DIRECTION INPUT ;
    USE SIGNAL ;
    SHAPE ABUTMENT ;
    PORT
      LAYER metal3 ;
      RECT 0.000 57.960 0.140 58.100 ;
    END
  END w0_wd_in[206]
  PIN w0_wd_in[207]
    DIRECTION INPUT ;
    USE SIGNAL ;
    SHAPE ABUTMENT ;
    PORT
      LAYER metal3 ;
      RECT 0.000 58.240 0.140 58.380 ;
    END
  END w0_wd_in[207]
  PIN w0_wd_in[208]
    DIRECTION INPUT ;
    USE SIGNAL ;
    SHAPE ABUTMENT ;
    PORT
      LAYER metal3 ;
      RECT 0.000 58.520 0.140 58.660 ;
    END
  END w0_wd_in[208]
  PIN w0_wd_in[209]
    DIRECTION INPUT ;
    USE SIGNAL ;
    SHAPE ABUTMENT ;
    PORT
      LAYER metal3 ;
      RECT 0.000 58.800 0.140 58.940 ;
    END
  END w0_wd_in[209]
  PIN w0_wd_in[210]
    DIRECTION INPUT ;
    USE SIGNAL ;
    SHAPE ABUTMENT ;
    PORT
      LAYER metal3 ;
      RECT 0.000 59.080 0.140 59.220 ;
    END
  END w0_wd_in[210]
  PIN w0_wd_in[211]
    DIRECTION INPUT ;
    USE SIGNAL ;
    SHAPE ABUTMENT ;
    PORT
      LAYER metal3 ;
      RECT 0.000 59.360 0.140 59.500 ;
    END
  END w0_wd_in[211]
  PIN w0_wd_in[212]
    DIRECTION INPUT ;
    USE SIGNAL ;
    SHAPE ABUTMENT ;
    PORT
      LAYER metal3 ;
      RECT 0.000 59.640 0.140 59.780 ;
    END
  END w0_wd_in[212]
  PIN w0_wd_in[213]
    DIRECTION INPUT ;
    USE SIGNAL ;
    SHAPE ABUTMENT ;
    PORT
      LAYER metal3 ;
      RECT 0.000 59.920 0.140 60.060 ;
    END
  END w0_wd_in[213]
  PIN w0_wd_in[214]
    DIRECTION INPUT ;
    USE SIGNAL ;
    SHAPE ABUTMENT ;
    PORT
      LAYER metal3 ;
      RECT 0.000 60.200 0.140 60.340 ;
    END
  END w0_wd_in[214]
  PIN w0_wd_in[215]
    DIRECTION INPUT ;
    USE SIGNAL ;
    SHAPE ABUTMENT ;
    PORT
      LAYER metal3 ;
      RECT 0.000 60.480 0.140 60.620 ;
    END
  END w0_wd_in[215]
  PIN w0_wd_in[216]
    DIRECTION INPUT ;
    USE SIGNAL ;
    SHAPE ABUTMENT ;
    PORT
      LAYER metal3 ;
      RECT 0.000 60.760 0.140 60.900 ;
    END
  END w0_wd_in[216]
  PIN w0_wd_in[217]
    DIRECTION INPUT ;
    USE SIGNAL ;
    SHAPE ABUTMENT ;
    PORT
      LAYER metal3 ;
      RECT 0.000 61.040 0.140 61.180 ;
    END
  END w0_wd_in[217]
  PIN w0_wd_in[218]
    DIRECTION INPUT ;
    USE SIGNAL ;
    SHAPE ABUTMENT ;
    PORT
      LAYER metal3 ;
      RECT 0.000 61.320 0.140 61.460 ;
    END
  END w0_wd_in[218]
  PIN w0_wd_in[219]
    DIRECTION INPUT ;
    USE SIGNAL ;
    SHAPE ABUTMENT ;
    PORT
      LAYER metal3 ;
      RECT 0.000 61.600 0.140 61.740 ;
    END
  END w0_wd_in[219]
  PIN w0_wd_in[220]
    DIRECTION INPUT ;
    USE SIGNAL ;
    SHAPE ABUTMENT ;
    PORT
      LAYER metal3 ;
      RECT 0.000 61.880 0.140 62.020 ;
    END
  END w0_wd_in[220]
  PIN w0_wd_in[221]
    DIRECTION INPUT ;
    USE SIGNAL ;
    SHAPE ABUTMENT ;
    PORT
      LAYER metal3 ;
      RECT 0.000 62.160 0.140 62.300 ;
    END
  END w0_wd_in[221]
  PIN w0_wd_in[222]
    DIRECTION INPUT ;
    USE SIGNAL ;
    SHAPE ABUTMENT ;
    PORT
      LAYER metal3 ;
      RECT 0.000 62.440 0.140 62.580 ;
    END
  END w0_wd_in[222]
  PIN w0_wd_in[223]
    DIRECTION INPUT ;
    USE SIGNAL ;
    SHAPE ABUTMENT ;
    PORT
      LAYER metal3 ;
      RECT 0.000 62.720 0.140 62.860 ;
    END
  END w0_wd_in[223]
  PIN w0_wd_in[224]
    DIRECTION INPUT ;
    USE SIGNAL ;
    SHAPE ABUTMENT ;
    PORT
      LAYER metal3 ;
      RECT 0.000 63.000 0.140 63.140 ;
    END
  END w0_wd_in[224]
  PIN w0_wd_in[225]
    DIRECTION INPUT ;
    USE SIGNAL ;
    SHAPE ABUTMENT ;
    PORT
      LAYER metal3 ;
      RECT 0.000 63.280 0.140 63.420 ;
    END
  END w0_wd_in[225]
  PIN w0_wd_in[226]
    DIRECTION INPUT ;
    USE SIGNAL ;
    SHAPE ABUTMENT ;
    PORT
      LAYER metal3 ;
      RECT 0.000 63.560 0.140 63.700 ;
    END
  END w0_wd_in[226]
  PIN w0_wd_in[227]
    DIRECTION INPUT ;
    USE SIGNAL ;
    SHAPE ABUTMENT ;
    PORT
      LAYER metal3 ;
      RECT 0.000 63.840 0.140 63.980 ;
    END
  END w0_wd_in[227]
  PIN w0_wd_in[228]
    DIRECTION INPUT ;
    USE SIGNAL ;
    SHAPE ABUTMENT ;
    PORT
      LAYER metal3 ;
      RECT 0.000 64.120 0.140 64.260 ;
    END
  END w0_wd_in[228]
  PIN w0_wd_in[229]
    DIRECTION INPUT ;
    USE SIGNAL ;
    SHAPE ABUTMENT ;
    PORT
      LAYER metal3 ;
      RECT 0.000 64.400 0.140 64.540 ;
    END
  END w0_wd_in[229]
  PIN w0_wd_in[230]
    DIRECTION INPUT ;
    USE SIGNAL ;
    SHAPE ABUTMENT ;
    PORT
      LAYER metal3 ;
      RECT 0.000 64.680 0.140 64.820 ;
    END
  END w0_wd_in[230]
  PIN w0_wd_in[231]
    DIRECTION INPUT ;
    USE SIGNAL ;
    SHAPE ABUTMENT ;
    PORT
      LAYER metal3 ;
      RECT 0.000 64.960 0.140 65.100 ;
    END
  END w0_wd_in[231]
  PIN w0_wd_in[232]
    DIRECTION INPUT ;
    USE SIGNAL ;
    SHAPE ABUTMENT ;
    PORT
      LAYER metal3 ;
      RECT 0.000 65.240 0.140 65.380 ;
    END
  END w0_wd_in[232]
  PIN w0_wd_in[233]
    DIRECTION INPUT ;
    USE SIGNAL ;
    SHAPE ABUTMENT ;
    PORT
      LAYER metal3 ;
      RECT 0.000 65.520 0.140 65.660 ;
    END
  END w0_wd_in[233]
  PIN w0_wd_in[234]
    DIRECTION INPUT ;
    USE SIGNAL ;
    SHAPE ABUTMENT ;
    PORT
      LAYER metal3 ;
      RECT 0.000 65.800 0.140 65.940 ;
    END
  END w0_wd_in[234]
  PIN w0_wd_in[235]
    DIRECTION INPUT ;
    USE SIGNAL ;
    SHAPE ABUTMENT ;
    PORT
      LAYER metal3 ;
      RECT 0.000 66.080 0.140 66.220 ;
    END
  END w0_wd_in[235]
  PIN w0_wd_in[236]
    DIRECTION INPUT ;
    USE SIGNAL ;
    SHAPE ABUTMENT ;
    PORT
      LAYER metal3 ;
      RECT 0.000 66.360 0.140 66.500 ;
    END
  END w0_wd_in[236]
  PIN w0_wd_in[237]
    DIRECTION INPUT ;
    USE SIGNAL ;
    SHAPE ABUTMENT ;
    PORT
      LAYER metal3 ;
      RECT 0.000 66.640 0.140 66.780 ;
    END
  END w0_wd_in[237]
  PIN w0_wd_in[238]
    DIRECTION INPUT ;
    USE SIGNAL ;
    SHAPE ABUTMENT ;
    PORT
      LAYER metal3 ;
      RECT 0.000 66.920 0.140 67.060 ;
    END
  END w0_wd_in[238]
  PIN w0_wd_in[239]
    DIRECTION INPUT ;
    USE SIGNAL ;
    SHAPE ABUTMENT ;
    PORT
      LAYER metal3 ;
      RECT 0.000 67.200 0.140 67.340 ;
    END
  END w0_wd_in[239]
  PIN w0_wd_in[240]
    DIRECTION INPUT ;
    USE SIGNAL ;
    SHAPE ABUTMENT ;
    PORT
      LAYER metal3 ;
      RECT 0.000 67.480 0.140 67.620 ;
    END
  END w0_wd_in[240]
  PIN w0_wd_in[241]
    DIRECTION INPUT ;
    USE SIGNAL ;
    SHAPE ABUTMENT ;
    PORT
      LAYER metal3 ;
      RECT 0.000 67.760 0.140 67.900 ;
    END
  END w0_wd_in[241]
  PIN w0_wd_in[242]
    DIRECTION INPUT ;
    USE SIGNAL ;
    SHAPE ABUTMENT ;
    PORT
      LAYER metal3 ;
      RECT 0.000 68.040 0.140 68.180 ;
    END
  END w0_wd_in[242]
  PIN w0_wd_in[243]
    DIRECTION INPUT ;
    USE SIGNAL ;
    SHAPE ABUTMENT ;
    PORT
      LAYER metal3 ;
      RECT 0.000 68.320 0.140 68.460 ;
    END
  END w0_wd_in[243]
  PIN w0_wd_in[244]
    DIRECTION INPUT ;
    USE SIGNAL ;
    SHAPE ABUTMENT ;
    PORT
      LAYER metal3 ;
      RECT 0.000 68.600 0.140 68.740 ;
    END
  END w0_wd_in[244]
  PIN w0_wd_in[245]
    DIRECTION INPUT ;
    USE SIGNAL ;
    SHAPE ABUTMENT ;
    PORT
      LAYER metal3 ;
      RECT 0.000 68.880 0.140 69.020 ;
    END
  END w0_wd_in[245]
  PIN w0_wd_in[246]
    DIRECTION INPUT ;
    USE SIGNAL ;
    SHAPE ABUTMENT ;
    PORT
      LAYER metal3 ;
      RECT 0.000 69.160 0.140 69.300 ;
    END
  END w0_wd_in[246]
  PIN w0_wd_in[247]
    DIRECTION INPUT ;
    USE SIGNAL ;
    SHAPE ABUTMENT ;
    PORT
      LAYER metal3 ;
      RECT 0.000 69.440 0.140 69.580 ;
    END
  END w0_wd_in[247]
  PIN w0_wd_in[248]
    DIRECTION INPUT ;
    USE SIGNAL ;
    SHAPE ABUTMENT ;
    PORT
      LAYER metal3 ;
      RECT 0.000 69.720 0.140 69.860 ;
    END
  END w0_wd_in[248]
  PIN w0_wd_in[249]
    DIRECTION INPUT ;
    USE SIGNAL ;
    SHAPE ABUTMENT ;
    PORT
      LAYER metal3 ;
      RECT 0.000 70.000 0.140 70.140 ;
    END
  END w0_wd_in[249]
  PIN w0_wd_in[250]
    DIRECTION INPUT ;
    USE SIGNAL ;
    SHAPE ABUTMENT ;
    PORT
      LAYER metal3 ;
      RECT 0.000 70.280 0.140 70.420 ;
    END
  END w0_wd_in[250]
  PIN w0_wd_in[251]
    DIRECTION INPUT ;
    USE SIGNAL ;
    SHAPE ABUTMENT ;
    PORT
      LAYER metal3 ;
      RECT 0.000 70.560 0.140 70.700 ;
    END
  END w0_wd_in[251]
  PIN w0_wd_in[252]
    DIRECTION INPUT ;
    USE SIGNAL ;
    SHAPE ABUTMENT ;
    PORT
      LAYER metal3 ;
      RECT 0.000 70.840 0.140 70.980 ;
    END
  END w0_wd_in[252]
  PIN w0_wd_in[253]
    DIRECTION INPUT ;
    USE SIGNAL ;
    SHAPE ABUTMENT ;
    PORT
      LAYER metal3 ;
      RECT 0.000 71.120 0.140 71.260 ;
    END
  END w0_wd_in[253]
  PIN w0_wd_in[254]
    DIRECTION INPUT ;
    USE SIGNAL ;
    SHAPE ABUTMENT ;
    PORT
      LAYER metal3 ;
      RECT 0.000 71.400 0.140 71.540 ;
    END
  END w0_wd_in[254]
  PIN w0_wd_in[255]
    DIRECTION INPUT ;
    USE SIGNAL ;
    SHAPE ABUTMENT ;
    PORT
      LAYER metal3 ;
      RECT 0.000 71.680 0.140 71.820 ;
    END
  END w0_wd_in[255]
  PIN w0_addr_in[0]
    DIRECTION INPUT ;
    USE SIGNAL ;
    SHAPE ABUTMENT ;
    PORT
      LAYER metal3 ;
      RECT 0.000 71.960 0.140 72.100 ;
    END
  END w0_addr_in[0]
  PIN w0_addr_in[1]
    DIRECTION INPUT ;
    USE SIGNAL ;
    SHAPE ABUTMENT ;
    PORT
      LAYER metal3 ;
      RECT 0.000 72.240 0.140 72.380 ;
    END
  END w0_addr_in[1]
  PIN w0_addr_in[2]
    DIRECTION INPUT ;
    USE SIGNAL ;
    SHAPE ABUTMENT ;
    PORT
      LAYER metal3 ;
      RECT 0.000 72.520 0.140 72.660 ;
    END
  END w0_addr_in[2]
  PIN w0_addr_in[3]
    DIRECTION INPUT ;
    USE SIGNAL ;
    SHAPE ABUTMENT ;
    PORT
      LAYER metal3 ;
      RECT 0.000 72.800 0.140 72.940 ;
    END
  END w0_addr_in[3]
  PIN w0_clk
    DIRECTION INPUT ;
    USE SIGNAL ;
    SHAPE ABUTMENT ;
    PORT
      LAYER metal3 ;
      RECT 0.000 73.080 0.140 73.220 ;
    END
  END w0_clk
  PIN w0_ce_in
    DIRECTION INPUT ;
    USE SIGNAL ;
    SHAPE ABUTMENT ;
    PORT
      LAYER metal3 ;
      RECT 0.000 73.360 0.140 73.500 ;
    END
  END w0_ce_in
  PIN w0_we_in
    DIRECTION INPUT ;
    USE SIGNAL ;
    SHAPE ABUTMENT ;
    PORT
      LAYER metal3 ;
      RECT 0.000 73.640 0.140 73.780 ;
    END
  END w0_we_in
  PIN r0_rd_out[0]
    DIRECTION OUTPUT ;
    USE SIGNAL ;
    SHAPE ABUTMENT ;
    PORT
      LAYER metal3 ;
      RECT 0.000 73.920 0.140 74.060 ;
    END
  END r0_rd_out[0]
  PIN r0_rd_out[1]
    DIRECTION OUTPUT ;
    USE SIGNAL ;
    SHAPE ABUTMENT ;
    PORT
      LAYER metal3 ;
      RECT 0.000 74.200 0.140 74.340 ;
    END
  END r0_rd_out[1]
  PIN r0_rd_out[2]
    DIRECTION OUTPUT ;
    USE SIGNAL ;
    SHAPE ABUTMENT ;
    PORT
      LAYER metal3 ;
      RECT 0.000 74.480 0.140 74.620 ;
    END
  END r0_rd_out[2]
  PIN r0_rd_out[3]
    DIRECTION OUTPUT ;
    USE SIGNAL ;
    SHAPE ABUTMENT ;
    PORT
      LAYER metal3 ;
      RECT 0.000 74.760 0.140 74.900 ;
    END
  END r0_rd_out[3]
  PIN r0_rd_out[4]
    DIRECTION OUTPUT ;
    USE SIGNAL ;
    SHAPE ABUTMENT ;
    PORT
      LAYER metal3 ;
      RECT 0.000 75.040 0.140 75.180 ;
    END
  END r0_rd_out[4]
  PIN r0_rd_out[5]
    DIRECTION OUTPUT ;
    USE SIGNAL ;
    SHAPE ABUTMENT ;
    PORT
      LAYER metal3 ;
      RECT 0.000 75.320 0.140 75.460 ;
    END
  END r0_rd_out[5]
  PIN r0_rd_out[6]
    DIRECTION OUTPUT ;
    USE SIGNAL ;
    SHAPE ABUTMENT ;
    PORT
      LAYER metal3 ;
      RECT 0.000 75.600 0.140 75.740 ;
    END
  END r0_rd_out[6]
  PIN r0_rd_out[7]
    DIRECTION OUTPUT ;
    USE SIGNAL ;
    SHAPE ABUTMENT ;
    PORT
      LAYER metal3 ;
      RECT 0.000 75.880 0.140 76.020 ;
    END
  END r0_rd_out[7]
  PIN r0_rd_out[8]
    DIRECTION OUTPUT ;
    USE SIGNAL ;
    SHAPE ABUTMENT ;
    PORT
      LAYER metal3 ;
      RECT 0.000 76.160 0.140 76.300 ;
    END
  END r0_rd_out[8]
  PIN r0_rd_out[9]
    DIRECTION OUTPUT ;
    USE SIGNAL ;
    SHAPE ABUTMENT ;
    PORT
      LAYER metal3 ;
      RECT 0.000 76.440 0.140 76.580 ;
    END
  END r0_rd_out[9]
  PIN r0_rd_out[10]
    DIRECTION OUTPUT ;
    USE SIGNAL ;
    SHAPE ABUTMENT ;
    PORT
      LAYER metal3 ;
      RECT 0.000 76.720 0.140 76.860 ;
    END
  END r0_rd_out[10]
  PIN r0_rd_out[11]
    DIRECTION OUTPUT ;
    USE SIGNAL ;
    SHAPE ABUTMENT ;
    PORT
      LAYER metal3 ;
      RECT 0.000 77.000 0.140 77.140 ;
    END
  END r0_rd_out[11]
  PIN r0_rd_out[12]
    DIRECTION OUTPUT ;
    USE SIGNAL ;
    SHAPE ABUTMENT ;
    PORT
      LAYER metal3 ;
      RECT 0.000 77.280 0.140 77.420 ;
    END
  END r0_rd_out[12]
  PIN r0_rd_out[13]
    DIRECTION OUTPUT ;
    USE SIGNAL ;
    SHAPE ABUTMENT ;
    PORT
      LAYER metal3 ;
      RECT 0.000 77.560 0.140 77.700 ;
    END
  END r0_rd_out[13]
  PIN r0_rd_out[14]
    DIRECTION OUTPUT ;
    USE SIGNAL ;
    SHAPE ABUTMENT ;
    PORT
      LAYER metal3 ;
      RECT 0.000 77.840 0.140 77.980 ;
    END
  END r0_rd_out[14]
  PIN r0_rd_out[15]
    DIRECTION OUTPUT ;
    USE SIGNAL ;
    SHAPE ABUTMENT ;
    PORT
      LAYER metal3 ;
      RECT 0.000 78.120 0.140 78.260 ;
    END
  END r0_rd_out[15]
  PIN r0_rd_out[16]
    DIRECTION OUTPUT ;
    USE SIGNAL ;
    SHAPE ABUTMENT ;
    PORT
      LAYER metal3 ;
      RECT 0.000 78.400 0.140 78.540 ;
    END
  END r0_rd_out[16]
  PIN r0_rd_out[17]
    DIRECTION OUTPUT ;
    USE SIGNAL ;
    SHAPE ABUTMENT ;
    PORT
      LAYER metal3 ;
      RECT 0.000 78.680 0.140 78.820 ;
    END
  END r0_rd_out[17]
  PIN r0_rd_out[18]
    DIRECTION OUTPUT ;
    USE SIGNAL ;
    SHAPE ABUTMENT ;
    PORT
      LAYER metal3 ;
      RECT 0.000 78.960 0.140 79.100 ;
    END
  END r0_rd_out[18]
  PIN r0_rd_out[19]
    DIRECTION OUTPUT ;
    USE SIGNAL ;
    SHAPE ABUTMENT ;
    PORT
      LAYER metal3 ;
      RECT 0.000 79.240 0.140 79.380 ;
    END
  END r0_rd_out[19]
  PIN r0_rd_out[20]
    DIRECTION OUTPUT ;
    USE SIGNAL ;
    SHAPE ABUTMENT ;
    PORT
      LAYER metal3 ;
      RECT 0.000 79.520 0.140 79.660 ;
    END
  END r0_rd_out[20]
  PIN r0_rd_out[21]
    DIRECTION OUTPUT ;
    USE SIGNAL ;
    SHAPE ABUTMENT ;
    PORT
      LAYER metal3 ;
      RECT 0.000 79.800 0.140 79.940 ;
    END
  END r0_rd_out[21]
  PIN r0_rd_out[22]
    DIRECTION OUTPUT ;
    USE SIGNAL ;
    SHAPE ABUTMENT ;
    PORT
      LAYER metal3 ;
      RECT 0.000 80.080 0.140 80.220 ;
    END
  END r0_rd_out[22]
  PIN r0_rd_out[23]
    DIRECTION OUTPUT ;
    USE SIGNAL ;
    SHAPE ABUTMENT ;
    PORT
      LAYER metal3 ;
      RECT 0.000 80.360 0.140 80.500 ;
    END
  END r0_rd_out[23]
  PIN r0_rd_out[24]
    DIRECTION OUTPUT ;
    USE SIGNAL ;
    SHAPE ABUTMENT ;
    PORT
      LAYER metal3 ;
      RECT 0.000 80.640 0.140 80.780 ;
    END
  END r0_rd_out[24]
  PIN r0_rd_out[25]
    DIRECTION OUTPUT ;
    USE SIGNAL ;
    SHAPE ABUTMENT ;
    PORT
      LAYER metal3 ;
      RECT 0.000 80.920 0.140 81.060 ;
    END
  END r0_rd_out[25]
  PIN r0_rd_out[26]
    DIRECTION OUTPUT ;
    USE SIGNAL ;
    SHAPE ABUTMENT ;
    PORT
      LAYER metal3 ;
      RECT 0.000 81.200 0.140 81.340 ;
    END
  END r0_rd_out[26]
  PIN r0_rd_out[27]
    DIRECTION OUTPUT ;
    USE SIGNAL ;
    SHAPE ABUTMENT ;
    PORT
      LAYER metal3 ;
      RECT 0.000 81.480 0.140 81.620 ;
    END
  END r0_rd_out[27]
  PIN r0_rd_out[28]
    DIRECTION OUTPUT ;
    USE SIGNAL ;
    SHAPE ABUTMENT ;
    PORT
      LAYER metal3 ;
      RECT 0.000 81.760 0.140 81.900 ;
    END
  END r0_rd_out[28]
  PIN r0_rd_out[29]
    DIRECTION OUTPUT ;
    USE SIGNAL ;
    SHAPE ABUTMENT ;
    PORT
      LAYER metal3 ;
      RECT 0.000 82.040 0.140 82.180 ;
    END
  END r0_rd_out[29]
  PIN r0_rd_out[30]
    DIRECTION OUTPUT ;
    USE SIGNAL ;
    SHAPE ABUTMENT ;
    PORT
      LAYER metal3 ;
      RECT 0.000 82.320 0.140 82.460 ;
    END
  END r0_rd_out[30]
  PIN r0_rd_out[31]
    DIRECTION OUTPUT ;
    USE SIGNAL ;
    SHAPE ABUTMENT ;
    PORT
      LAYER metal3 ;
      RECT 0.000 82.600 0.140 82.740 ;
    END
  END r0_rd_out[31]
  PIN r0_rd_out[32]
    DIRECTION OUTPUT ;
    USE SIGNAL ;
    SHAPE ABUTMENT ;
    PORT
      LAYER metal3 ;
      RECT 0.000 82.880 0.140 83.020 ;
    END
  END r0_rd_out[32]
  PIN r0_rd_out[33]
    DIRECTION OUTPUT ;
    USE SIGNAL ;
    SHAPE ABUTMENT ;
    PORT
      LAYER metal3 ;
      RECT 0.000 83.160 0.140 83.300 ;
    END
  END r0_rd_out[33]
  PIN r0_rd_out[34]
    DIRECTION OUTPUT ;
    USE SIGNAL ;
    SHAPE ABUTMENT ;
    PORT
      LAYER metal3 ;
      RECT 0.000 83.440 0.140 83.580 ;
    END
  END r0_rd_out[34]
  PIN r0_rd_out[35]
    DIRECTION OUTPUT ;
    USE SIGNAL ;
    SHAPE ABUTMENT ;
    PORT
      LAYER metal3 ;
      RECT 0.000 83.720 0.140 83.860 ;
    END
  END r0_rd_out[35]
  PIN r0_rd_out[36]
    DIRECTION OUTPUT ;
    USE SIGNAL ;
    SHAPE ABUTMENT ;
    PORT
      LAYER metal3 ;
      RECT 0.000 84.000 0.140 84.140 ;
    END
  END r0_rd_out[36]
  PIN r0_rd_out[37]
    DIRECTION OUTPUT ;
    USE SIGNAL ;
    SHAPE ABUTMENT ;
    PORT
      LAYER metal3 ;
      RECT 0.000 84.280 0.140 84.420 ;
    END
  END r0_rd_out[37]
  PIN r0_rd_out[38]
    DIRECTION OUTPUT ;
    USE SIGNAL ;
    SHAPE ABUTMENT ;
    PORT
      LAYER metal3 ;
      RECT 0.000 84.560 0.140 84.700 ;
    END
  END r0_rd_out[38]
  PIN r0_rd_out[39]
    DIRECTION OUTPUT ;
    USE SIGNAL ;
    SHAPE ABUTMENT ;
    PORT
      LAYER metal3 ;
      RECT 0.000 84.840 0.140 84.980 ;
    END
  END r0_rd_out[39]
  PIN r0_rd_out[40]
    DIRECTION OUTPUT ;
    USE SIGNAL ;
    SHAPE ABUTMENT ;
    PORT
      LAYER metal3 ;
      RECT 0.000 85.120 0.140 85.260 ;
    END
  END r0_rd_out[40]
  PIN r0_rd_out[41]
    DIRECTION OUTPUT ;
    USE SIGNAL ;
    SHAPE ABUTMENT ;
    PORT
      LAYER metal3 ;
      RECT 0.000 85.400 0.140 85.540 ;
    END
  END r0_rd_out[41]
  PIN r0_rd_out[42]
    DIRECTION OUTPUT ;
    USE SIGNAL ;
    SHAPE ABUTMENT ;
    PORT
      LAYER metal3 ;
      RECT 0.000 85.680 0.140 85.820 ;
    END
  END r0_rd_out[42]
  PIN r0_rd_out[43]
    DIRECTION OUTPUT ;
    USE SIGNAL ;
    SHAPE ABUTMENT ;
    PORT
      LAYER metal3 ;
      RECT 0.000 85.960 0.140 86.100 ;
    END
  END r0_rd_out[43]
  PIN r0_rd_out[44]
    DIRECTION OUTPUT ;
    USE SIGNAL ;
    SHAPE ABUTMENT ;
    PORT
      LAYER metal3 ;
      RECT 0.000 86.240 0.140 86.380 ;
    END
  END r0_rd_out[44]
  PIN r0_rd_out[45]
    DIRECTION OUTPUT ;
    USE SIGNAL ;
    SHAPE ABUTMENT ;
    PORT
      LAYER metal3 ;
      RECT 0.000 86.520 0.140 86.660 ;
    END
  END r0_rd_out[45]
  PIN r0_rd_out[46]
    DIRECTION OUTPUT ;
    USE SIGNAL ;
    SHAPE ABUTMENT ;
    PORT
      LAYER metal3 ;
      RECT 0.000 86.800 0.140 86.940 ;
    END
  END r0_rd_out[46]
  PIN r0_rd_out[47]
    DIRECTION OUTPUT ;
    USE SIGNAL ;
    SHAPE ABUTMENT ;
    PORT
      LAYER metal3 ;
      RECT 0.000 87.080 0.140 87.220 ;
    END
  END r0_rd_out[47]
  PIN r0_rd_out[48]
    DIRECTION OUTPUT ;
    USE SIGNAL ;
    SHAPE ABUTMENT ;
    PORT
      LAYER metal3 ;
      RECT 0.000 87.360 0.140 87.500 ;
    END
  END r0_rd_out[48]
  PIN r0_rd_out[49]
    DIRECTION OUTPUT ;
    USE SIGNAL ;
    SHAPE ABUTMENT ;
    PORT
      LAYER metal3 ;
      RECT 0.000 87.640 0.140 87.780 ;
    END
  END r0_rd_out[49]
  PIN r0_rd_out[50]
    DIRECTION OUTPUT ;
    USE SIGNAL ;
    SHAPE ABUTMENT ;
    PORT
      LAYER metal3 ;
      RECT 0.000 87.920 0.140 88.060 ;
    END
  END r0_rd_out[50]
  PIN r0_rd_out[51]
    DIRECTION OUTPUT ;
    USE SIGNAL ;
    SHAPE ABUTMENT ;
    PORT
      LAYER metal3 ;
      RECT 0.000 88.200 0.140 88.340 ;
    END
  END r0_rd_out[51]
  PIN r0_rd_out[52]
    DIRECTION OUTPUT ;
    USE SIGNAL ;
    SHAPE ABUTMENT ;
    PORT
      LAYER metal3 ;
      RECT 0.000 88.480 0.140 88.620 ;
    END
  END r0_rd_out[52]
  PIN r0_rd_out[53]
    DIRECTION OUTPUT ;
    USE SIGNAL ;
    SHAPE ABUTMENT ;
    PORT
      LAYER metal3 ;
      RECT 0.000 88.760 0.140 88.900 ;
    END
  END r0_rd_out[53]
  PIN r0_rd_out[54]
    DIRECTION OUTPUT ;
    USE SIGNAL ;
    SHAPE ABUTMENT ;
    PORT
      LAYER metal3 ;
      RECT 0.000 89.040 0.140 89.180 ;
    END
  END r0_rd_out[54]
  PIN r0_rd_out[55]
    DIRECTION OUTPUT ;
    USE SIGNAL ;
    SHAPE ABUTMENT ;
    PORT
      LAYER metal3 ;
      RECT 0.000 89.320 0.140 89.460 ;
    END
  END r0_rd_out[55]
  PIN r0_rd_out[56]
    DIRECTION OUTPUT ;
    USE SIGNAL ;
    SHAPE ABUTMENT ;
    PORT
      LAYER metal3 ;
      RECT 0.000 89.600 0.140 89.740 ;
    END
  END r0_rd_out[56]
  PIN r0_rd_out[57]
    DIRECTION OUTPUT ;
    USE SIGNAL ;
    SHAPE ABUTMENT ;
    PORT
      LAYER metal3 ;
      RECT 0.000 89.880 0.140 90.020 ;
    END
  END r0_rd_out[57]
  PIN r0_rd_out[58]
    DIRECTION OUTPUT ;
    USE SIGNAL ;
    SHAPE ABUTMENT ;
    PORT
      LAYER metal3 ;
      RECT 0.000 90.160 0.140 90.300 ;
    END
  END r0_rd_out[58]
  PIN r0_rd_out[59]
    DIRECTION OUTPUT ;
    USE SIGNAL ;
    SHAPE ABUTMENT ;
    PORT
      LAYER metal3 ;
      RECT 0.000 90.440 0.140 90.580 ;
    END
  END r0_rd_out[59]
  PIN r0_rd_out[60]
    DIRECTION OUTPUT ;
    USE SIGNAL ;
    SHAPE ABUTMENT ;
    PORT
      LAYER metal3 ;
      RECT 0.000 90.720 0.140 90.860 ;
    END
  END r0_rd_out[60]
  PIN r0_rd_out[61]
    DIRECTION OUTPUT ;
    USE SIGNAL ;
    SHAPE ABUTMENT ;
    PORT
      LAYER metal3 ;
      RECT 0.000 91.000 0.140 91.140 ;
    END
  END r0_rd_out[61]
  PIN r0_rd_out[62]
    DIRECTION OUTPUT ;
    USE SIGNAL ;
    SHAPE ABUTMENT ;
    PORT
      LAYER metal3 ;
      RECT 0.000 91.280 0.140 91.420 ;
    END
  END r0_rd_out[62]
  PIN r0_rd_out[63]
    DIRECTION OUTPUT ;
    USE SIGNAL ;
    SHAPE ABUTMENT ;
    PORT
      LAYER metal3 ;
      RECT 0.000 91.560 0.140 91.700 ;
    END
  END r0_rd_out[63]
  PIN r0_rd_out[64]
    DIRECTION OUTPUT ;
    USE SIGNAL ;
    SHAPE ABUTMENT ;
    PORT
      LAYER metal3 ;
      RECT 0.000 91.840 0.140 91.980 ;
    END
  END r0_rd_out[64]
  PIN r0_rd_out[65]
    DIRECTION OUTPUT ;
    USE SIGNAL ;
    SHAPE ABUTMENT ;
    PORT
      LAYER metal3 ;
      RECT 0.000 92.120 0.140 92.260 ;
    END
  END r0_rd_out[65]
  PIN r0_rd_out[66]
    DIRECTION OUTPUT ;
    USE SIGNAL ;
    SHAPE ABUTMENT ;
    PORT
      LAYER metal3 ;
      RECT 0.000 92.400 0.140 92.540 ;
    END
  END r0_rd_out[66]
  PIN r0_rd_out[67]
    DIRECTION OUTPUT ;
    USE SIGNAL ;
    SHAPE ABUTMENT ;
    PORT
      LAYER metal3 ;
      RECT 0.000 92.680 0.140 92.820 ;
    END
  END r0_rd_out[67]
  PIN r0_rd_out[68]
    DIRECTION OUTPUT ;
    USE SIGNAL ;
    SHAPE ABUTMENT ;
    PORT
      LAYER metal3 ;
      RECT 0.000 92.960 0.140 93.100 ;
    END
  END r0_rd_out[68]
  PIN r0_rd_out[69]
    DIRECTION OUTPUT ;
    USE SIGNAL ;
    SHAPE ABUTMENT ;
    PORT
      LAYER metal3 ;
      RECT 0.000 93.240 0.140 93.380 ;
    END
  END r0_rd_out[69]
  PIN r0_rd_out[70]
    DIRECTION OUTPUT ;
    USE SIGNAL ;
    SHAPE ABUTMENT ;
    PORT
      LAYER metal3 ;
      RECT 0.000 93.520 0.140 93.660 ;
    END
  END r0_rd_out[70]
  PIN r0_rd_out[71]
    DIRECTION OUTPUT ;
    USE SIGNAL ;
    SHAPE ABUTMENT ;
    PORT
      LAYER metal3 ;
      RECT 0.000 93.800 0.140 93.940 ;
    END
  END r0_rd_out[71]
  PIN r0_rd_out[72]
    DIRECTION OUTPUT ;
    USE SIGNAL ;
    SHAPE ABUTMENT ;
    PORT
      LAYER metal3 ;
      RECT 0.000 94.080 0.140 94.220 ;
    END
  END r0_rd_out[72]
  PIN r0_rd_out[73]
    DIRECTION OUTPUT ;
    USE SIGNAL ;
    SHAPE ABUTMENT ;
    PORT
      LAYER metal3 ;
      RECT 0.000 94.360 0.140 94.500 ;
    END
  END r0_rd_out[73]
  PIN r0_rd_out[74]
    DIRECTION OUTPUT ;
    USE SIGNAL ;
    SHAPE ABUTMENT ;
    PORT
      LAYER metal3 ;
      RECT 0.000 94.640 0.140 94.780 ;
    END
  END r0_rd_out[74]
  PIN r0_rd_out[75]
    DIRECTION OUTPUT ;
    USE SIGNAL ;
    SHAPE ABUTMENT ;
    PORT
      LAYER metal3 ;
      RECT 0.000 94.920 0.140 95.060 ;
    END
  END r0_rd_out[75]
  PIN r0_rd_out[76]
    DIRECTION OUTPUT ;
    USE SIGNAL ;
    SHAPE ABUTMENT ;
    PORT
      LAYER metal3 ;
      RECT 0.000 95.200 0.140 95.340 ;
    END
  END r0_rd_out[76]
  PIN r0_rd_out[77]
    DIRECTION OUTPUT ;
    USE SIGNAL ;
    SHAPE ABUTMENT ;
    PORT
      LAYER metal3 ;
      RECT 0.000 95.480 0.140 95.620 ;
    END
  END r0_rd_out[77]
  PIN r0_rd_out[78]
    DIRECTION OUTPUT ;
    USE SIGNAL ;
    SHAPE ABUTMENT ;
    PORT
      LAYER metal3 ;
      RECT 0.000 95.760 0.140 95.900 ;
    END
  END r0_rd_out[78]
  PIN r0_rd_out[79]
    DIRECTION OUTPUT ;
    USE SIGNAL ;
    SHAPE ABUTMENT ;
    PORT
      LAYER metal3 ;
      RECT 0.000 96.040 0.140 96.180 ;
    END
  END r0_rd_out[79]
  PIN r0_rd_out[80]
    DIRECTION OUTPUT ;
    USE SIGNAL ;
    SHAPE ABUTMENT ;
    PORT
      LAYER metal3 ;
      RECT 0.000 96.320 0.140 96.460 ;
    END
  END r0_rd_out[80]
  PIN r0_rd_out[81]
    DIRECTION OUTPUT ;
    USE SIGNAL ;
    SHAPE ABUTMENT ;
    PORT
      LAYER metal3 ;
      RECT 0.000 96.600 0.140 96.740 ;
    END
  END r0_rd_out[81]
  PIN r0_rd_out[82]
    DIRECTION OUTPUT ;
    USE SIGNAL ;
    SHAPE ABUTMENT ;
    PORT
      LAYER metal3 ;
      RECT 0.000 96.880 0.140 97.020 ;
    END
  END r0_rd_out[82]
  PIN r0_rd_out[83]
    DIRECTION OUTPUT ;
    USE SIGNAL ;
    SHAPE ABUTMENT ;
    PORT
      LAYER metal3 ;
      RECT 0.000 97.160 0.140 97.300 ;
    END
  END r0_rd_out[83]
  PIN r0_rd_out[84]
    DIRECTION OUTPUT ;
    USE SIGNAL ;
    SHAPE ABUTMENT ;
    PORT
      LAYER metal3 ;
      RECT 0.000 97.440 0.140 97.580 ;
    END
  END r0_rd_out[84]
  PIN r0_rd_out[85]
    DIRECTION OUTPUT ;
    USE SIGNAL ;
    SHAPE ABUTMENT ;
    PORT
      LAYER metal3 ;
      RECT 0.000 97.720 0.140 97.860 ;
    END
  END r0_rd_out[85]
  PIN r0_rd_out[86]
    DIRECTION OUTPUT ;
    USE SIGNAL ;
    SHAPE ABUTMENT ;
    PORT
      LAYER metal3 ;
      RECT 0.000 98.000 0.140 98.140 ;
    END
  END r0_rd_out[86]
  PIN r0_rd_out[87]
    DIRECTION OUTPUT ;
    USE SIGNAL ;
    SHAPE ABUTMENT ;
    PORT
      LAYER metal3 ;
      RECT 0.000 98.280 0.140 98.420 ;
    END
  END r0_rd_out[87]
  PIN r0_rd_out[88]
    DIRECTION OUTPUT ;
    USE SIGNAL ;
    SHAPE ABUTMENT ;
    PORT
      LAYER metal3 ;
      RECT 0.000 98.560 0.140 98.700 ;
    END
  END r0_rd_out[88]
  PIN r0_rd_out[89]
    DIRECTION OUTPUT ;
    USE SIGNAL ;
    SHAPE ABUTMENT ;
    PORT
      LAYER metal3 ;
      RECT 0.000 98.840 0.140 98.980 ;
    END
  END r0_rd_out[89]
  PIN r0_rd_out[90]
    DIRECTION OUTPUT ;
    USE SIGNAL ;
    SHAPE ABUTMENT ;
    PORT
      LAYER metal3 ;
      RECT 0.000 99.120 0.140 99.260 ;
    END
  END r0_rd_out[90]
  PIN r0_rd_out[91]
    DIRECTION OUTPUT ;
    USE SIGNAL ;
    SHAPE ABUTMENT ;
    PORT
      LAYER metal3 ;
      RECT 0.000 99.400 0.140 99.540 ;
    END
  END r0_rd_out[91]
  PIN r0_rd_out[92]
    DIRECTION OUTPUT ;
    USE SIGNAL ;
    SHAPE ABUTMENT ;
    PORT
      LAYER metal3 ;
      RECT 0.000 99.680 0.140 99.820 ;
    END
  END r0_rd_out[92]
  PIN r0_rd_out[93]
    DIRECTION OUTPUT ;
    USE SIGNAL ;
    SHAPE ABUTMENT ;
    PORT
      LAYER metal3 ;
      RECT 0.000 99.960 0.140 100.100 ;
    END
  END r0_rd_out[93]
  PIN r0_rd_out[94]
    DIRECTION OUTPUT ;
    USE SIGNAL ;
    SHAPE ABUTMENT ;
    PORT
      LAYER metal3 ;
      RECT 0.000 100.240 0.140 100.380 ;
    END
  END r0_rd_out[94]
  PIN r0_rd_out[95]
    DIRECTION OUTPUT ;
    USE SIGNAL ;
    SHAPE ABUTMENT ;
    PORT
      LAYER metal3 ;
      RECT 0.000 100.520 0.140 100.660 ;
    END
  END r0_rd_out[95]
  PIN r0_rd_out[96]
    DIRECTION OUTPUT ;
    USE SIGNAL ;
    SHAPE ABUTMENT ;
    PORT
      LAYER metal3 ;
      RECT 0.000 100.800 0.140 100.940 ;
    END
  END r0_rd_out[96]
  PIN r0_rd_out[97]
    DIRECTION OUTPUT ;
    USE SIGNAL ;
    SHAPE ABUTMENT ;
    PORT
      LAYER metal3 ;
      RECT 0.000 101.080 0.140 101.220 ;
    END
  END r0_rd_out[97]
  PIN r0_rd_out[98]
    DIRECTION OUTPUT ;
    USE SIGNAL ;
    SHAPE ABUTMENT ;
    PORT
      LAYER metal3 ;
      RECT 0.000 101.360 0.140 101.500 ;
    END
  END r0_rd_out[98]
  PIN r0_rd_out[99]
    DIRECTION OUTPUT ;
    USE SIGNAL ;
    SHAPE ABUTMENT ;
    PORT
      LAYER metal3 ;
      RECT 0.000 101.640 0.140 101.780 ;
    END
  END r0_rd_out[99]
  PIN r0_rd_out[100]
    DIRECTION OUTPUT ;
    USE SIGNAL ;
    SHAPE ABUTMENT ;
    PORT
      LAYER metal3 ;
      RECT 0.000 101.920 0.140 102.060 ;
    END
  END r0_rd_out[100]
  PIN r0_rd_out[101]
    DIRECTION OUTPUT ;
    USE SIGNAL ;
    SHAPE ABUTMENT ;
    PORT
      LAYER metal3 ;
      RECT 0.000 102.200 0.140 102.340 ;
    END
  END r0_rd_out[101]
  PIN r0_rd_out[102]
    DIRECTION OUTPUT ;
    USE SIGNAL ;
    SHAPE ABUTMENT ;
    PORT
      LAYER metal3 ;
      RECT 0.000 102.480 0.140 102.620 ;
    END
  END r0_rd_out[102]
  PIN r0_rd_out[103]
    DIRECTION OUTPUT ;
    USE SIGNAL ;
    SHAPE ABUTMENT ;
    PORT
      LAYER metal3 ;
      RECT 0.000 102.760 0.140 102.900 ;
    END
  END r0_rd_out[103]
  PIN r0_rd_out[104]
    DIRECTION OUTPUT ;
    USE SIGNAL ;
    SHAPE ABUTMENT ;
    PORT
      LAYER metal3 ;
      RECT 0.000 103.040 0.140 103.180 ;
    END
  END r0_rd_out[104]
  PIN r0_rd_out[105]
    DIRECTION OUTPUT ;
    USE SIGNAL ;
    SHAPE ABUTMENT ;
    PORT
      LAYER metal3 ;
      RECT 0.000 103.320 0.140 103.460 ;
    END
  END r0_rd_out[105]
  PIN r0_rd_out[106]
    DIRECTION OUTPUT ;
    USE SIGNAL ;
    SHAPE ABUTMENT ;
    PORT
      LAYER metal3 ;
      RECT 0.000 103.600 0.140 103.740 ;
    END
  END r0_rd_out[106]
  PIN r0_rd_out[107]
    DIRECTION OUTPUT ;
    USE SIGNAL ;
    SHAPE ABUTMENT ;
    PORT
      LAYER metal3 ;
      RECT 0.000 103.880 0.140 104.020 ;
    END
  END r0_rd_out[107]
  PIN r0_rd_out[108]
    DIRECTION OUTPUT ;
    USE SIGNAL ;
    SHAPE ABUTMENT ;
    PORT
      LAYER metal3 ;
      RECT 0.000 104.160 0.140 104.300 ;
    END
  END r0_rd_out[108]
  PIN r0_rd_out[109]
    DIRECTION OUTPUT ;
    USE SIGNAL ;
    SHAPE ABUTMENT ;
    PORT
      LAYER metal3 ;
      RECT 0.000 104.440 0.140 104.580 ;
    END
  END r0_rd_out[109]
  PIN r0_rd_out[110]
    DIRECTION OUTPUT ;
    USE SIGNAL ;
    SHAPE ABUTMENT ;
    PORT
      LAYER metal3 ;
      RECT 0.000 104.720 0.140 104.860 ;
    END
  END r0_rd_out[110]
  PIN r0_rd_out[111]
    DIRECTION OUTPUT ;
    USE SIGNAL ;
    SHAPE ABUTMENT ;
    PORT
      LAYER metal3 ;
      RECT 0.000 105.000 0.140 105.140 ;
    END
  END r0_rd_out[111]
  PIN r0_rd_out[112]
    DIRECTION OUTPUT ;
    USE SIGNAL ;
    SHAPE ABUTMENT ;
    PORT
      LAYER metal3 ;
      RECT 0.000 105.280 0.140 105.420 ;
    END
  END r0_rd_out[112]
  PIN r0_rd_out[113]
    DIRECTION OUTPUT ;
    USE SIGNAL ;
    SHAPE ABUTMENT ;
    PORT
      LAYER metal3 ;
      RECT 0.000 105.560 0.140 105.700 ;
    END
  END r0_rd_out[113]
  PIN r0_rd_out[114]
    DIRECTION OUTPUT ;
    USE SIGNAL ;
    SHAPE ABUTMENT ;
    PORT
      LAYER metal3 ;
      RECT 0.000 105.840 0.140 105.980 ;
    END
  END r0_rd_out[114]
  PIN r0_rd_out[115]
    DIRECTION OUTPUT ;
    USE SIGNAL ;
    SHAPE ABUTMENT ;
    PORT
      LAYER metal3 ;
      RECT 0.000 106.120 0.140 106.260 ;
    END
  END r0_rd_out[115]
  PIN r0_rd_out[116]
    DIRECTION OUTPUT ;
    USE SIGNAL ;
    SHAPE ABUTMENT ;
    PORT
      LAYER metal3 ;
      RECT 0.000 106.400 0.140 106.540 ;
    END
  END r0_rd_out[116]
  PIN r0_rd_out[117]
    DIRECTION OUTPUT ;
    USE SIGNAL ;
    SHAPE ABUTMENT ;
    PORT
      LAYER metal3 ;
      RECT 0.000 106.680 0.140 106.820 ;
    END
  END r0_rd_out[117]
  PIN r0_rd_out[118]
    DIRECTION OUTPUT ;
    USE SIGNAL ;
    SHAPE ABUTMENT ;
    PORT
      LAYER metal3 ;
      RECT 0.000 106.960 0.140 107.100 ;
    END
  END r0_rd_out[118]
  PIN r0_rd_out[119]
    DIRECTION OUTPUT ;
    USE SIGNAL ;
    SHAPE ABUTMENT ;
    PORT
      LAYER metal3 ;
      RECT 0.000 107.240 0.140 107.380 ;
    END
  END r0_rd_out[119]
  PIN r0_rd_out[120]
    DIRECTION OUTPUT ;
    USE SIGNAL ;
    SHAPE ABUTMENT ;
    PORT
      LAYER metal3 ;
      RECT 0.000 107.520 0.140 107.660 ;
    END
  END r0_rd_out[120]
  PIN r0_rd_out[121]
    DIRECTION OUTPUT ;
    USE SIGNAL ;
    SHAPE ABUTMENT ;
    PORT
      LAYER metal3 ;
      RECT 0.000 107.800 0.140 107.940 ;
    END
  END r0_rd_out[121]
  PIN r0_rd_out[122]
    DIRECTION OUTPUT ;
    USE SIGNAL ;
    SHAPE ABUTMENT ;
    PORT
      LAYER metal3 ;
      RECT 0.000 108.080 0.140 108.220 ;
    END
  END r0_rd_out[122]
  PIN r0_rd_out[123]
    DIRECTION OUTPUT ;
    USE SIGNAL ;
    SHAPE ABUTMENT ;
    PORT
      LAYER metal3 ;
      RECT 0.000 108.360 0.140 108.500 ;
    END
  END r0_rd_out[123]
  PIN r0_rd_out[124]
    DIRECTION OUTPUT ;
    USE SIGNAL ;
    SHAPE ABUTMENT ;
    PORT
      LAYER metal3 ;
      RECT 0.000 108.640 0.140 108.780 ;
    END
  END r0_rd_out[124]
  PIN r0_rd_out[125]
    DIRECTION OUTPUT ;
    USE SIGNAL ;
    SHAPE ABUTMENT ;
    PORT
      LAYER metal3 ;
      RECT 0.000 108.920 0.140 109.060 ;
    END
  END r0_rd_out[125]
  PIN r0_rd_out[126]
    DIRECTION OUTPUT ;
    USE SIGNAL ;
    SHAPE ABUTMENT ;
    PORT
      LAYER metal3 ;
      RECT 0.000 109.200 0.140 109.340 ;
    END
  END r0_rd_out[126]
  PIN r0_rd_out[127]
    DIRECTION OUTPUT ;
    USE SIGNAL ;
    SHAPE ABUTMENT ;
    PORT
      LAYER metal3 ;
      RECT 0.000 109.480 0.140 109.620 ;
    END
  END r0_rd_out[127]
  PIN r0_rd_out[128]
    DIRECTION OUTPUT ;
    USE SIGNAL ;
    SHAPE ABUTMENT ;
    PORT
      LAYER metal3 ;
      RECT 0.000 109.760 0.140 109.900 ;
    END
  END r0_rd_out[128]
  PIN r0_rd_out[129]
    DIRECTION OUTPUT ;
    USE SIGNAL ;
    SHAPE ABUTMENT ;
    PORT
      LAYER metal3 ;
      RECT 0.000 110.040 0.140 110.180 ;
    END
  END r0_rd_out[129]
  PIN r0_rd_out[130]
    DIRECTION OUTPUT ;
    USE SIGNAL ;
    SHAPE ABUTMENT ;
    PORT
      LAYER metal3 ;
      RECT 0.000 110.320 0.140 110.460 ;
    END
  END r0_rd_out[130]
  PIN r0_rd_out[131]
    DIRECTION OUTPUT ;
    USE SIGNAL ;
    SHAPE ABUTMENT ;
    PORT
      LAYER metal3 ;
      RECT 0.000 110.600 0.140 110.740 ;
    END
  END r0_rd_out[131]
  PIN r0_rd_out[132]
    DIRECTION OUTPUT ;
    USE SIGNAL ;
    SHAPE ABUTMENT ;
    PORT
      LAYER metal3 ;
      RECT 0.000 110.880 0.140 111.020 ;
    END
  END r0_rd_out[132]
  PIN r0_rd_out[133]
    DIRECTION OUTPUT ;
    USE SIGNAL ;
    SHAPE ABUTMENT ;
    PORT
      LAYER metal3 ;
      RECT 0.000 111.160 0.140 111.300 ;
    END
  END r0_rd_out[133]
  PIN r0_rd_out[134]
    DIRECTION OUTPUT ;
    USE SIGNAL ;
    SHAPE ABUTMENT ;
    PORT
      LAYER metal3 ;
      RECT 0.000 111.440 0.140 111.580 ;
    END
  END r0_rd_out[134]
  PIN r0_rd_out[135]
    DIRECTION OUTPUT ;
    USE SIGNAL ;
    SHAPE ABUTMENT ;
    PORT
      LAYER metal3 ;
      RECT 0.000 111.720 0.140 111.860 ;
    END
  END r0_rd_out[135]
  PIN r0_rd_out[136]
    DIRECTION OUTPUT ;
    USE SIGNAL ;
    SHAPE ABUTMENT ;
    PORT
      LAYER metal3 ;
      RECT 0.000 112.000 0.140 112.140 ;
    END
  END r0_rd_out[136]
  PIN r0_rd_out[137]
    DIRECTION OUTPUT ;
    USE SIGNAL ;
    SHAPE ABUTMENT ;
    PORT
      LAYER metal3 ;
      RECT 0.000 112.280 0.140 112.420 ;
    END
  END r0_rd_out[137]
  PIN r0_rd_out[138]
    DIRECTION OUTPUT ;
    USE SIGNAL ;
    SHAPE ABUTMENT ;
    PORT
      LAYER metal3 ;
      RECT 0.000 112.560 0.140 112.700 ;
    END
  END r0_rd_out[138]
  PIN r0_rd_out[139]
    DIRECTION OUTPUT ;
    USE SIGNAL ;
    SHAPE ABUTMENT ;
    PORT
      LAYER metal3 ;
      RECT 0.000 112.840 0.140 112.980 ;
    END
  END r0_rd_out[139]
  PIN r0_rd_out[140]
    DIRECTION OUTPUT ;
    USE SIGNAL ;
    SHAPE ABUTMENT ;
    PORT
      LAYER metal3 ;
      RECT 0.000 113.120 0.140 113.260 ;
    END
  END r0_rd_out[140]
  PIN r0_rd_out[141]
    DIRECTION OUTPUT ;
    USE SIGNAL ;
    SHAPE ABUTMENT ;
    PORT
      LAYER metal3 ;
      RECT 0.000 113.400 0.140 113.540 ;
    END
  END r0_rd_out[141]
  PIN r0_rd_out[142]
    DIRECTION OUTPUT ;
    USE SIGNAL ;
    SHAPE ABUTMENT ;
    PORT
      LAYER metal3 ;
      RECT 0.000 113.680 0.140 113.820 ;
    END
  END r0_rd_out[142]
  PIN r0_rd_out[143]
    DIRECTION OUTPUT ;
    USE SIGNAL ;
    SHAPE ABUTMENT ;
    PORT
      LAYER metal3 ;
      RECT 0.000 113.960 0.140 114.100 ;
    END
  END r0_rd_out[143]
  PIN r0_rd_out[144]
    DIRECTION OUTPUT ;
    USE SIGNAL ;
    SHAPE ABUTMENT ;
    PORT
      LAYER metal3 ;
      RECT 0.000 114.240 0.140 114.380 ;
    END
  END r0_rd_out[144]
  PIN r0_rd_out[145]
    DIRECTION OUTPUT ;
    USE SIGNAL ;
    SHAPE ABUTMENT ;
    PORT
      LAYER metal3 ;
      RECT 0.000 114.520 0.140 114.660 ;
    END
  END r0_rd_out[145]
  PIN r0_rd_out[146]
    DIRECTION OUTPUT ;
    USE SIGNAL ;
    SHAPE ABUTMENT ;
    PORT
      LAYER metal3 ;
      RECT 0.000 114.800 0.140 114.940 ;
    END
  END r0_rd_out[146]
  PIN r0_rd_out[147]
    DIRECTION OUTPUT ;
    USE SIGNAL ;
    SHAPE ABUTMENT ;
    PORT
      LAYER metal3 ;
      RECT 0.000 115.080 0.140 115.220 ;
    END
  END r0_rd_out[147]
  PIN r0_rd_out[148]
    DIRECTION OUTPUT ;
    USE SIGNAL ;
    SHAPE ABUTMENT ;
    PORT
      LAYER metal3 ;
      RECT 0.000 115.360 0.140 115.500 ;
    END
  END r0_rd_out[148]
  PIN r0_rd_out[149]
    DIRECTION OUTPUT ;
    USE SIGNAL ;
    SHAPE ABUTMENT ;
    PORT
      LAYER metal3 ;
      RECT 0.000 115.640 0.140 115.780 ;
    END
  END r0_rd_out[149]
  PIN r0_rd_out[150]
    DIRECTION OUTPUT ;
    USE SIGNAL ;
    SHAPE ABUTMENT ;
    PORT
      LAYER metal3 ;
      RECT 0.000 115.920 0.140 116.060 ;
    END
  END r0_rd_out[150]
  PIN r0_rd_out[151]
    DIRECTION OUTPUT ;
    USE SIGNAL ;
    SHAPE ABUTMENT ;
    PORT
      LAYER metal3 ;
      RECT 0.000 116.200 0.140 116.340 ;
    END
  END r0_rd_out[151]
  PIN r0_rd_out[152]
    DIRECTION OUTPUT ;
    USE SIGNAL ;
    SHAPE ABUTMENT ;
    PORT
      LAYER metal3 ;
      RECT 0.000 116.480 0.140 116.620 ;
    END
  END r0_rd_out[152]
  PIN r0_rd_out[153]
    DIRECTION OUTPUT ;
    USE SIGNAL ;
    SHAPE ABUTMENT ;
    PORT
      LAYER metal3 ;
      RECT 0.000 116.760 0.140 116.900 ;
    END
  END r0_rd_out[153]
  PIN r0_rd_out[154]
    DIRECTION OUTPUT ;
    USE SIGNAL ;
    SHAPE ABUTMENT ;
    PORT
      LAYER metal3 ;
      RECT 0.000 117.040 0.140 117.180 ;
    END
  END r0_rd_out[154]
  PIN r0_rd_out[155]
    DIRECTION OUTPUT ;
    USE SIGNAL ;
    SHAPE ABUTMENT ;
    PORT
      LAYER metal3 ;
      RECT 0.000 117.320 0.140 117.460 ;
    END
  END r0_rd_out[155]
  PIN r0_rd_out[156]
    DIRECTION OUTPUT ;
    USE SIGNAL ;
    SHAPE ABUTMENT ;
    PORT
      LAYER metal3 ;
      RECT 0.000 117.600 0.140 117.740 ;
    END
  END r0_rd_out[156]
  PIN r0_rd_out[157]
    DIRECTION OUTPUT ;
    USE SIGNAL ;
    SHAPE ABUTMENT ;
    PORT
      LAYER metal3 ;
      RECT 0.000 117.880 0.140 118.020 ;
    END
  END r0_rd_out[157]
  PIN r0_rd_out[158]
    DIRECTION OUTPUT ;
    USE SIGNAL ;
    SHAPE ABUTMENT ;
    PORT
      LAYER metal3 ;
      RECT 0.000 118.160 0.140 118.300 ;
    END
  END r0_rd_out[158]
  PIN r0_rd_out[159]
    DIRECTION OUTPUT ;
    USE SIGNAL ;
    SHAPE ABUTMENT ;
    PORT
      LAYER metal3 ;
      RECT 0.000 118.440 0.140 118.580 ;
    END
  END r0_rd_out[159]
  PIN r0_rd_out[160]
    DIRECTION OUTPUT ;
    USE SIGNAL ;
    SHAPE ABUTMENT ;
    PORT
      LAYER metal3 ;
      RECT 0.000 118.720 0.140 118.860 ;
    END
  END r0_rd_out[160]
  PIN r0_rd_out[161]
    DIRECTION OUTPUT ;
    USE SIGNAL ;
    SHAPE ABUTMENT ;
    PORT
      LAYER metal3 ;
      RECT 0.000 119.000 0.140 119.140 ;
    END
  END r0_rd_out[161]
  PIN r0_rd_out[162]
    DIRECTION OUTPUT ;
    USE SIGNAL ;
    SHAPE ABUTMENT ;
    PORT
      LAYER metal3 ;
      RECT 0.000 119.280 0.140 119.420 ;
    END
  END r0_rd_out[162]
  PIN r0_rd_out[163]
    DIRECTION OUTPUT ;
    USE SIGNAL ;
    SHAPE ABUTMENT ;
    PORT
      LAYER metal3 ;
      RECT 0.000 119.560 0.140 119.700 ;
    END
  END r0_rd_out[163]
  PIN r0_rd_out[164]
    DIRECTION OUTPUT ;
    USE SIGNAL ;
    SHAPE ABUTMENT ;
    PORT
      LAYER metal3 ;
      RECT 0.000 119.840 0.140 119.980 ;
    END
  END r0_rd_out[164]
  PIN r0_rd_out[165]
    DIRECTION OUTPUT ;
    USE SIGNAL ;
    SHAPE ABUTMENT ;
    PORT
      LAYER metal3 ;
      RECT 0.000 120.120 0.140 120.260 ;
    END
  END r0_rd_out[165]
  PIN r0_rd_out[166]
    DIRECTION OUTPUT ;
    USE SIGNAL ;
    SHAPE ABUTMENT ;
    PORT
      LAYER metal3 ;
      RECT 0.000 120.400 0.140 120.540 ;
    END
  END r0_rd_out[166]
  PIN r0_rd_out[167]
    DIRECTION OUTPUT ;
    USE SIGNAL ;
    SHAPE ABUTMENT ;
    PORT
      LAYER metal3 ;
      RECT 0.000 120.680 0.140 120.820 ;
    END
  END r0_rd_out[167]
  PIN r0_rd_out[168]
    DIRECTION OUTPUT ;
    USE SIGNAL ;
    SHAPE ABUTMENT ;
    PORT
      LAYER metal3 ;
      RECT 0.000 120.960 0.140 121.100 ;
    END
  END r0_rd_out[168]
  PIN r0_rd_out[169]
    DIRECTION OUTPUT ;
    USE SIGNAL ;
    SHAPE ABUTMENT ;
    PORT
      LAYER metal3 ;
      RECT 0.000 121.240 0.140 121.380 ;
    END
  END r0_rd_out[169]
  PIN r0_rd_out[170]
    DIRECTION OUTPUT ;
    USE SIGNAL ;
    SHAPE ABUTMENT ;
    PORT
      LAYER metal3 ;
      RECT 0.000 121.520 0.140 121.660 ;
    END
  END r0_rd_out[170]
  PIN r0_rd_out[171]
    DIRECTION OUTPUT ;
    USE SIGNAL ;
    SHAPE ABUTMENT ;
    PORT
      LAYER metal3 ;
      RECT 0.000 121.800 0.140 121.940 ;
    END
  END r0_rd_out[171]
  PIN r0_rd_out[172]
    DIRECTION OUTPUT ;
    USE SIGNAL ;
    SHAPE ABUTMENT ;
    PORT
      LAYER metal3 ;
      RECT 0.000 122.080 0.140 122.220 ;
    END
  END r0_rd_out[172]
  PIN r0_rd_out[173]
    DIRECTION OUTPUT ;
    USE SIGNAL ;
    SHAPE ABUTMENT ;
    PORT
      LAYER metal3 ;
      RECT 0.000 122.360 0.140 122.500 ;
    END
  END r0_rd_out[173]
  PIN r0_rd_out[174]
    DIRECTION OUTPUT ;
    USE SIGNAL ;
    SHAPE ABUTMENT ;
    PORT
      LAYER metal3 ;
      RECT 0.000 122.640 0.140 122.780 ;
    END
  END r0_rd_out[174]
  PIN r0_rd_out[175]
    DIRECTION OUTPUT ;
    USE SIGNAL ;
    SHAPE ABUTMENT ;
    PORT
      LAYER metal3 ;
      RECT 0.000 122.920 0.140 123.060 ;
    END
  END r0_rd_out[175]
  PIN r0_rd_out[176]
    DIRECTION OUTPUT ;
    USE SIGNAL ;
    SHAPE ABUTMENT ;
    PORT
      LAYER metal3 ;
      RECT 0.000 123.200 0.140 123.340 ;
    END
  END r0_rd_out[176]
  PIN r0_rd_out[177]
    DIRECTION OUTPUT ;
    USE SIGNAL ;
    SHAPE ABUTMENT ;
    PORT
      LAYER metal3 ;
      RECT 0.000 123.480 0.140 123.620 ;
    END
  END r0_rd_out[177]
  PIN r0_rd_out[178]
    DIRECTION OUTPUT ;
    USE SIGNAL ;
    SHAPE ABUTMENT ;
    PORT
      LAYER metal3 ;
      RECT 0.000 123.760 0.140 123.900 ;
    END
  END r0_rd_out[178]
  PIN r0_rd_out[179]
    DIRECTION OUTPUT ;
    USE SIGNAL ;
    SHAPE ABUTMENT ;
    PORT
      LAYER metal3 ;
      RECT 0.000 124.040 0.140 124.180 ;
    END
  END r0_rd_out[179]
  PIN r0_rd_out[180]
    DIRECTION OUTPUT ;
    USE SIGNAL ;
    SHAPE ABUTMENT ;
    PORT
      LAYER metal3 ;
      RECT 0.000 124.320 0.140 124.460 ;
    END
  END r0_rd_out[180]
  PIN r0_rd_out[181]
    DIRECTION OUTPUT ;
    USE SIGNAL ;
    SHAPE ABUTMENT ;
    PORT
      LAYER metal3 ;
      RECT 0.000 124.600 0.140 124.740 ;
    END
  END r0_rd_out[181]
  PIN r0_rd_out[182]
    DIRECTION OUTPUT ;
    USE SIGNAL ;
    SHAPE ABUTMENT ;
    PORT
      LAYER metal3 ;
      RECT 0.000 124.880 0.140 125.020 ;
    END
  END r0_rd_out[182]
  PIN r0_rd_out[183]
    DIRECTION OUTPUT ;
    USE SIGNAL ;
    SHAPE ABUTMENT ;
    PORT
      LAYER metal3 ;
      RECT 0.000 125.160 0.140 125.300 ;
    END
  END r0_rd_out[183]
  PIN r0_rd_out[184]
    DIRECTION OUTPUT ;
    USE SIGNAL ;
    SHAPE ABUTMENT ;
    PORT
      LAYER metal3 ;
      RECT 0.000 125.440 0.140 125.580 ;
    END
  END r0_rd_out[184]
  PIN r0_rd_out[185]
    DIRECTION OUTPUT ;
    USE SIGNAL ;
    SHAPE ABUTMENT ;
    PORT
      LAYER metal3 ;
      RECT 0.000 125.720 0.140 125.860 ;
    END
  END r0_rd_out[185]
  PIN r0_rd_out[186]
    DIRECTION OUTPUT ;
    USE SIGNAL ;
    SHAPE ABUTMENT ;
    PORT
      LAYER metal3 ;
      RECT 0.000 126.000 0.140 126.140 ;
    END
  END r0_rd_out[186]
  PIN r0_rd_out[187]
    DIRECTION OUTPUT ;
    USE SIGNAL ;
    SHAPE ABUTMENT ;
    PORT
      LAYER metal3 ;
      RECT 0.000 126.280 0.140 126.420 ;
    END
  END r0_rd_out[187]
  PIN r0_rd_out[188]
    DIRECTION OUTPUT ;
    USE SIGNAL ;
    SHAPE ABUTMENT ;
    PORT
      LAYER metal3 ;
      RECT 0.000 126.560 0.140 126.700 ;
    END
  END r0_rd_out[188]
  PIN r0_rd_out[189]
    DIRECTION OUTPUT ;
    USE SIGNAL ;
    SHAPE ABUTMENT ;
    PORT
      LAYER metal3 ;
      RECT 0.000 126.840 0.140 126.980 ;
    END
  END r0_rd_out[189]
  PIN r0_rd_out[190]
    DIRECTION OUTPUT ;
    USE SIGNAL ;
    SHAPE ABUTMENT ;
    PORT
      LAYER metal3 ;
      RECT 0.000 127.120 0.140 127.260 ;
    END
  END r0_rd_out[190]
  PIN r0_rd_out[191]
    DIRECTION OUTPUT ;
    USE SIGNAL ;
    SHAPE ABUTMENT ;
    PORT
      LAYER metal3 ;
      RECT 0.000 127.400 0.140 127.540 ;
    END
  END r0_rd_out[191]
  PIN r0_rd_out[192]
    DIRECTION OUTPUT ;
    USE SIGNAL ;
    SHAPE ABUTMENT ;
    PORT
      LAYER metal3 ;
      RECT 0.000 127.680 0.140 127.820 ;
    END
  END r0_rd_out[192]
  PIN r0_rd_out[193]
    DIRECTION OUTPUT ;
    USE SIGNAL ;
    SHAPE ABUTMENT ;
    PORT
      LAYER metal3 ;
      RECT 0.000 127.960 0.140 128.100 ;
    END
  END r0_rd_out[193]
  PIN r0_rd_out[194]
    DIRECTION OUTPUT ;
    USE SIGNAL ;
    SHAPE ABUTMENT ;
    PORT
      LAYER metal3 ;
      RECT 0.000 128.240 0.140 128.380 ;
    END
  END r0_rd_out[194]
  PIN r0_rd_out[195]
    DIRECTION OUTPUT ;
    USE SIGNAL ;
    SHAPE ABUTMENT ;
    PORT
      LAYER metal3 ;
      RECT 0.000 128.520 0.140 128.660 ;
    END
  END r0_rd_out[195]
  PIN r0_rd_out[196]
    DIRECTION OUTPUT ;
    USE SIGNAL ;
    SHAPE ABUTMENT ;
    PORT
      LAYER metal3 ;
      RECT 0.000 128.800 0.140 128.940 ;
    END
  END r0_rd_out[196]
  PIN r0_rd_out[197]
    DIRECTION OUTPUT ;
    USE SIGNAL ;
    SHAPE ABUTMENT ;
    PORT
      LAYER metal3 ;
      RECT 0.000 129.080 0.140 129.220 ;
    END
  END r0_rd_out[197]
  PIN r0_rd_out[198]
    DIRECTION OUTPUT ;
    USE SIGNAL ;
    SHAPE ABUTMENT ;
    PORT
      LAYER metal3 ;
      RECT 0.000 129.360 0.140 129.500 ;
    END
  END r0_rd_out[198]
  PIN r0_rd_out[199]
    DIRECTION OUTPUT ;
    USE SIGNAL ;
    SHAPE ABUTMENT ;
    PORT
      LAYER metal3 ;
      RECT 0.000 129.640 0.140 129.780 ;
    END
  END r0_rd_out[199]
  PIN r0_rd_out[200]
    DIRECTION OUTPUT ;
    USE SIGNAL ;
    SHAPE ABUTMENT ;
    PORT
      LAYER metal3 ;
      RECT 0.000 129.920 0.140 130.060 ;
    END
  END r0_rd_out[200]
  PIN r0_rd_out[201]
    DIRECTION OUTPUT ;
    USE SIGNAL ;
    SHAPE ABUTMENT ;
    PORT
      LAYER metal3 ;
      RECT 0.000 130.200 0.140 130.340 ;
    END
  END r0_rd_out[201]
  PIN r0_rd_out[202]
    DIRECTION OUTPUT ;
    USE SIGNAL ;
    SHAPE ABUTMENT ;
    PORT
      LAYER metal3 ;
      RECT 0.000 130.480 0.140 130.620 ;
    END
  END r0_rd_out[202]
  PIN r0_rd_out[203]
    DIRECTION OUTPUT ;
    USE SIGNAL ;
    SHAPE ABUTMENT ;
    PORT
      LAYER metal3 ;
      RECT 0.000 130.760 0.140 130.900 ;
    END
  END r0_rd_out[203]
  PIN r0_rd_out[204]
    DIRECTION OUTPUT ;
    USE SIGNAL ;
    SHAPE ABUTMENT ;
    PORT
      LAYER metal3 ;
      RECT 0.000 131.040 0.140 131.180 ;
    END
  END r0_rd_out[204]
  PIN r0_rd_out[205]
    DIRECTION OUTPUT ;
    USE SIGNAL ;
    SHAPE ABUTMENT ;
    PORT
      LAYER metal3 ;
      RECT 0.000 131.320 0.140 131.460 ;
    END
  END r0_rd_out[205]
  PIN r0_rd_out[206]
    DIRECTION OUTPUT ;
    USE SIGNAL ;
    SHAPE ABUTMENT ;
    PORT
      LAYER metal3 ;
      RECT 0.000 131.600 0.140 131.740 ;
    END
  END r0_rd_out[206]
  PIN r0_rd_out[207]
    DIRECTION OUTPUT ;
    USE SIGNAL ;
    SHAPE ABUTMENT ;
    PORT
      LAYER metal3 ;
      RECT 0.000 131.880 0.140 132.020 ;
    END
  END r0_rd_out[207]
  PIN r0_rd_out[208]
    DIRECTION OUTPUT ;
    USE SIGNAL ;
    SHAPE ABUTMENT ;
    PORT
      LAYER metal3 ;
      RECT 0.000 132.160 0.140 132.300 ;
    END
  END r0_rd_out[208]
  PIN r0_rd_out[209]
    DIRECTION OUTPUT ;
    USE SIGNAL ;
    SHAPE ABUTMENT ;
    PORT
      LAYER metal3 ;
      RECT 0.000 132.440 0.140 132.580 ;
    END
  END r0_rd_out[209]
  PIN r0_rd_out[210]
    DIRECTION OUTPUT ;
    USE SIGNAL ;
    SHAPE ABUTMENT ;
    PORT
      LAYER metal3 ;
      RECT 0.000 132.720 0.140 132.860 ;
    END
  END r0_rd_out[210]
  PIN r0_rd_out[211]
    DIRECTION OUTPUT ;
    USE SIGNAL ;
    SHAPE ABUTMENT ;
    PORT
      LAYER metal3 ;
      RECT 0.000 133.000 0.140 133.140 ;
    END
  END r0_rd_out[211]
  PIN r0_rd_out[212]
    DIRECTION OUTPUT ;
    USE SIGNAL ;
    SHAPE ABUTMENT ;
    PORT
      LAYER metal3 ;
      RECT 0.000 133.280 0.140 133.420 ;
    END
  END r0_rd_out[212]
  PIN r0_rd_out[213]
    DIRECTION OUTPUT ;
    USE SIGNAL ;
    SHAPE ABUTMENT ;
    PORT
      LAYER metal3 ;
      RECT 0.000 133.560 0.140 133.700 ;
    END
  END r0_rd_out[213]
  PIN r0_rd_out[214]
    DIRECTION OUTPUT ;
    USE SIGNAL ;
    SHAPE ABUTMENT ;
    PORT
      LAYER metal3 ;
      RECT 0.000 133.840 0.140 133.980 ;
    END
  END r0_rd_out[214]
  PIN r0_rd_out[215]
    DIRECTION OUTPUT ;
    USE SIGNAL ;
    SHAPE ABUTMENT ;
    PORT
      LAYER metal3 ;
      RECT 0.000 134.120 0.140 134.260 ;
    END
  END r0_rd_out[215]
  PIN r0_rd_out[216]
    DIRECTION OUTPUT ;
    USE SIGNAL ;
    SHAPE ABUTMENT ;
    PORT
      LAYER metal3 ;
      RECT 0.000 134.400 0.140 134.540 ;
    END
  END r0_rd_out[216]
  PIN r0_rd_out[217]
    DIRECTION OUTPUT ;
    USE SIGNAL ;
    SHAPE ABUTMENT ;
    PORT
      LAYER metal3 ;
      RECT 0.000 134.680 0.140 134.820 ;
    END
  END r0_rd_out[217]
  PIN r0_rd_out[218]
    DIRECTION OUTPUT ;
    USE SIGNAL ;
    SHAPE ABUTMENT ;
    PORT
      LAYER metal3 ;
      RECT 0.000 134.960 0.140 135.100 ;
    END
  END r0_rd_out[218]
  PIN r0_rd_out[219]
    DIRECTION OUTPUT ;
    USE SIGNAL ;
    SHAPE ABUTMENT ;
    PORT
      LAYER metal3 ;
      RECT 0.000 135.240 0.140 135.380 ;
    END
  END r0_rd_out[219]
  PIN r0_rd_out[220]
    DIRECTION OUTPUT ;
    USE SIGNAL ;
    SHAPE ABUTMENT ;
    PORT
      LAYER metal3 ;
      RECT 0.000 135.520 0.140 135.660 ;
    END
  END r0_rd_out[220]
  PIN r0_rd_out[221]
    DIRECTION OUTPUT ;
    USE SIGNAL ;
    SHAPE ABUTMENT ;
    PORT
      LAYER metal3 ;
      RECT 0.000 135.800 0.140 135.940 ;
    END
  END r0_rd_out[221]
  PIN r0_rd_out[222]
    DIRECTION OUTPUT ;
    USE SIGNAL ;
    SHAPE ABUTMENT ;
    PORT
      LAYER metal3 ;
      RECT 0.000 136.080 0.140 136.220 ;
    END
  END r0_rd_out[222]
  PIN r0_rd_out[223]
    DIRECTION OUTPUT ;
    USE SIGNAL ;
    SHAPE ABUTMENT ;
    PORT
      LAYER metal3 ;
      RECT 0.000 136.360 0.140 136.500 ;
    END
  END r0_rd_out[223]
  PIN r0_rd_out[224]
    DIRECTION OUTPUT ;
    USE SIGNAL ;
    SHAPE ABUTMENT ;
    PORT
      LAYER metal3 ;
      RECT 0.000 136.640 0.140 136.780 ;
    END
  END r0_rd_out[224]
  PIN r0_rd_out[225]
    DIRECTION OUTPUT ;
    USE SIGNAL ;
    SHAPE ABUTMENT ;
    PORT
      LAYER metal3 ;
      RECT 0.000 136.920 0.140 137.060 ;
    END
  END r0_rd_out[225]
  PIN r0_rd_out[226]
    DIRECTION OUTPUT ;
    USE SIGNAL ;
    SHAPE ABUTMENT ;
    PORT
      LAYER metal3 ;
      RECT 0.000 137.200 0.140 137.340 ;
    END
  END r0_rd_out[226]
  PIN r0_rd_out[227]
    DIRECTION OUTPUT ;
    USE SIGNAL ;
    SHAPE ABUTMENT ;
    PORT
      LAYER metal3 ;
      RECT 0.000 137.480 0.140 137.620 ;
    END
  END r0_rd_out[227]
  PIN r0_rd_out[228]
    DIRECTION OUTPUT ;
    USE SIGNAL ;
    SHAPE ABUTMENT ;
    PORT
      LAYER metal3 ;
      RECT 0.000 137.760 0.140 137.900 ;
    END
  END r0_rd_out[228]
  PIN r0_rd_out[229]
    DIRECTION OUTPUT ;
    USE SIGNAL ;
    SHAPE ABUTMENT ;
    PORT
      LAYER metal3 ;
      RECT 0.000 138.040 0.140 138.180 ;
    END
  END r0_rd_out[229]
  PIN r0_rd_out[230]
    DIRECTION OUTPUT ;
    USE SIGNAL ;
    SHAPE ABUTMENT ;
    PORT
      LAYER metal3 ;
      RECT 0.000 138.320 0.140 138.460 ;
    END
  END r0_rd_out[230]
  PIN r0_rd_out[231]
    DIRECTION OUTPUT ;
    USE SIGNAL ;
    SHAPE ABUTMENT ;
    PORT
      LAYER metal3 ;
      RECT 0.000 138.600 0.140 138.740 ;
    END
  END r0_rd_out[231]
  PIN r0_rd_out[232]
    DIRECTION OUTPUT ;
    USE SIGNAL ;
    SHAPE ABUTMENT ;
    PORT
      LAYER metal3 ;
      RECT 0.000 138.880 0.140 139.020 ;
    END
  END r0_rd_out[232]
  PIN r0_rd_out[233]
    DIRECTION OUTPUT ;
    USE SIGNAL ;
    SHAPE ABUTMENT ;
    PORT
      LAYER metal3 ;
      RECT 0.000 139.160 0.140 139.300 ;
    END
  END r0_rd_out[233]
  PIN r0_rd_out[234]
    DIRECTION OUTPUT ;
    USE SIGNAL ;
    SHAPE ABUTMENT ;
    PORT
      LAYER metal3 ;
      RECT 0.000 139.440 0.140 139.580 ;
    END
  END r0_rd_out[234]
  PIN r0_rd_out[235]
    DIRECTION OUTPUT ;
    USE SIGNAL ;
    SHAPE ABUTMENT ;
    PORT
      LAYER metal3 ;
      RECT 0.000 139.720 0.140 139.860 ;
    END
  END r0_rd_out[235]
  PIN r0_rd_out[236]
    DIRECTION OUTPUT ;
    USE SIGNAL ;
    SHAPE ABUTMENT ;
    PORT
      LAYER metal3 ;
      RECT 0.000 140.000 0.140 140.140 ;
    END
  END r0_rd_out[236]
  PIN r0_rd_out[237]
    DIRECTION OUTPUT ;
    USE SIGNAL ;
    SHAPE ABUTMENT ;
    PORT
      LAYER metal3 ;
      RECT 0.000 140.280 0.140 140.420 ;
    END
  END r0_rd_out[237]
  PIN r0_rd_out[238]
    DIRECTION OUTPUT ;
    USE SIGNAL ;
    SHAPE ABUTMENT ;
    PORT
      LAYER metal3 ;
      RECT 0.000 140.560 0.140 140.700 ;
    END
  END r0_rd_out[238]
  PIN r0_rd_out[239]
    DIRECTION OUTPUT ;
    USE SIGNAL ;
    SHAPE ABUTMENT ;
    PORT
      LAYER metal3 ;
      RECT 0.000 140.840 0.140 140.980 ;
    END
  END r0_rd_out[239]
  PIN r0_rd_out[240]
    DIRECTION OUTPUT ;
    USE SIGNAL ;
    SHAPE ABUTMENT ;
    PORT
      LAYER metal3 ;
      RECT 0.000 141.120 0.140 141.260 ;
    END
  END r0_rd_out[240]
  PIN r0_rd_out[241]
    DIRECTION OUTPUT ;
    USE SIGNAL ;
    SHAPE ABUTMENT ;
    PORT
      LAYER metal3 ;
      RECT 0.000 141.400 0.140 141.540 ;
    END
  END r0_rd_out[241]
  PIN r0_rd_out[242]
    DIRECTION OUTPUT ;
    USE SIGNAL ;
    SHAPE ABUTMENT ;
    PORT
      LAYER metal3 ;
      RECT 0.000 141.680 0.140 141.820 ;
    END
  END r0_rd_out[242]
  PIN r0_rd_out[243]
    DIRECTION OUTPUT ;
    USE SIGNAL ;
    SHAPE ABUTMENT ;
    PORT
      LAYER metal3 ;
      RECT 0.000 141.960 0.140 142.100 ;
    END
  END r0_rd_out[243]
  PIN r0_rd_out[244]
    DIRECTION OUTPUT ;
    USE SIGNAL ;
    SHAPE ABUTMENT ;
    PORT
      LAYER metal3 ;
      RECT 0.000 142.240 0.140 142.380 ;
    END
  END r0_rd_out[244]
  PIN r0_rd_out[245]
    DIRECTION OUTPUT ;
    USE SIGNAL ;
    SHAPE ABUTMENT ;
    PORT
      LAYER metal3 ;
      RECT 0.000 142.520 0.140 142.660 ;
    END
  END r0_rd_out[245]
  PIN r0_rd_out[246]
    DIRECTION OUTPUT ;
    USE SIGNAL ;
    SHAPE ABUTMENT ;
    PORT
      LAYER metal3 ;
      RECT 0.000 142.800 0.140 142.940 ;
    END
  END r0_rd_out[246]
  PIN r0_rd_out[247]
    DIRECTION OUTPUT ;
    USE SIGNAL ;
    SHAPE ABUTMENT ;
    PORT
      LAYER metal3 ;
      RECT 0.000 143.080 0.140 143.220 ;
    END
  END r0_rd_out[247]
  PIN r0_rd_out[248]
    DIRECTION OUTPUT ;
    USE SIGNAL ;
    SHAPE ABUTMENT ;
    PORT
      LAYER metal3 ;
      RECT 0.000 143.360 0.140 143.500 ;
    END
  END r0_rd_out[248]
  PIN r0_rd_out[249]
    DIRECTION OUTPUT ;
    USE SIGNAL ;
    SHAPE ABUTMENT ;
    PORT
      LAYER metal3 ;
      RECT 0.000 143.640 0.140 143.780 ;
    END
  END r0_rd_out[249]
  PIN r0_rd_out[250]
    DIRECTION OUTPUT ;
    USE SIGNAL ;
    SHAPE ABUTMENT ;
    PORT
      LAYER metal3 ;
      RECT 0.000 143.920 0.140 144.060 ;
    END
  END r0_rd_out[250]
  PIN r0_rd_out[251]
    DIRECTION OUTPUT ;
    USE SIGNAL ;
    SHAPE ABUTMENT ;
    PORT
      LAYER metal3 ;
      RECT 0.000 144.200 0.140 144.340 ;
    END
  END r0_rd_out[251]
  PIN r0_rd_out[252]
    DIRECTION OUTPUT ;
    USE SIGNAL ;
    SHAPE ABUTMENT ;
    PORT
      LAYER metal3 ;
      RECT 0.000 144.480 0.140 144.620 ;
    END
  END r0_rd_out[252]
  PIN r0_rd_out[253]
    DIRECTION OUTPUT ;
    USE SIGNAL ;
    SHAPE ABUTMENT ;
    PORT
      LAYER metal3 ;
      RECT 0.000 144.760 0.140 144.900 ;
    END
  END r0_rd_out[253]
  PIN r0_rd_out[254]
    DIRECTION OUTPUT ;
    USE SIGNAL ;
    SHAPE ABUTMENT ;
    PORT
      LAYER metal3 ;
      RECT 0.000 145.040 0.140 145.180 ;
    END
  END r0_rd_out[254]
  PIN r0_rd_out[255]
    DIRECTION OUTPUT ;
    USE SIGNAL ;
    SHAPE ABUTMENT ;
    PORT
      LAYER metal3 ;
      RECT 0.000 145.320 0.140 145.460 ;
    END
  END r0_rd_out[255]
  PIN r0_addr_in[0]
    DIRECTION INPUT ;
    USE SIGNAL ;
    SHAPE ABUTMENT ;
    PORT
      LAYER metal3 ;
      RECT 0.000 145.600 0.140 145.740 ;
    END
  END r0_addr_in[0]
  PIN r0_addr_in[1]
    DIRECTION INPUT ;
    USE SIGNAL ;
    SHAPE ABUTMENT ;
    PORT
      LAYER metal3 ;
      RECT 0.000 145.880 0.140 146.020 ;
    END
  END r0_addr_in[1]
  PIN r0_addr_in[2]
    DIRECTION INPUT ;
    USE SIGNAL ;
    SHAPE ABUTMENT ;
    PORT
      LAYER metal3 ;
      RECT 0.000 146.160 0.140 146.300 ;
    END
  END r0_addr_in[2]
  PIN r0_addr_in[3]
    DIRECTION INPUT ;
    USE SIGNAL ;
    SHAPE ABUTMENT ;
    PORT
      LAYER metal3 ;
      RECT 0.000 146.440 0.140 146.580 ;
    END
  END r0_addr_in[3]
  PIN r0_clk
    DIRECTION INPUT ;
    USE SIGNAL ;
    SHAPE ABUTMENT ;
    PORT
      LAYER metal3 ;
      RECT 0.000 146.720 0.140 146.860 ;
    END
  END r0_clk
  PIN r0_ce_in
    DIRECTION INPUT ;
    USE SIGNAL ;
    SHAPE ABUTMENT ;
    PORT
      LAYER metal3 ;
      RECT 0.000 147.000 0.140 147.140 ;
    END
  END r0_ce_in
  PIN VDD
    DIRECTION INOUT ;
    USE POWER ;
    PORT
      LAYER metal4 ;
      RECT 0.190 0.000 176.320 0.140 ;
      RECT 0.190 0.560 176.320 0.700 ;
      RECT 0.190 1.120 176.320 1.260 ;
      RECT 0.190 1.680 176.320 1.820 ;
      RECT 0.190 2.240 176.320 2.380 ;
      RECT 0.190 2.800 176.320 2.940 ;
      RECT 0.190 3.360 176.320 3.500 ;
      RECT 0.190 3.920 176.320 4.060 ;
      RECT 0.190 4.480 176.320 4.620 ;
      RECT 0.190 5.040 176.320 5.180 ;
      RECT 0.190 5.600 176.320 5.740 ;
      RECT 0.190 6.160 176.320 6.300 ;
      RECT 0.190 6.720 176.320 6.860 ;
      RECT 0.190 7.280 176.320 7.420 ;
      RECT 0.190 7.840 176.320 7.980 ;
      RECT 0.190 8.400 176.320 8.540 ;
      RECT 0.190 8.960 176.320 9.100 ;
      RECT 0.190 9.520 176.320 9.660 ;
      RECT 0.190 10.080 176.320 10.220 ;
      RECT 0.190 10.640 176.320 10.780 ;
      RECT 0.190 11.200 176.320 11.340 ;
      RECT 0.190 11.760 176.320 11.900 ;
      RECT 0.190 12.320 176.320 12.460 ;
      RECT 0.190 12.880 176.320 13.020 ;
      RECT 0.190 13.440 176.320 13.580 ;
      RECT 0.190 14.000 176.320 14.140 ;
      RECT 0.190 14.560 176.320 14.700 ;
      RECT 0.190 15.120 176.320 15.260 ;
      RECT 0.190 15.680 176.320 15.820 ;
      RECT 0.190 16.240 176.320 16.380 ;
      RECT 0.190 16.800 176.320 16.940 ;
      RECT 0.190 17.360 176.320 17.500 ;
      RECT 0.190 17.920 176.320 18.060 ;
      RECT 0.190 18.480 176.320 18.620 ;
      RECT 0.190 19.040 176.320 19.180 ;
      RECT 0.190 19.600 176.320 19.740 ;
      RECT 0.190 20.160 176.320 20.300 ;
      RECT 0.190 20.720 176.320 20.860 ;
      RECT 0.190 21.280 176.320 21.420 ;
      RECT 0.190 21.840 176.320 21.980 ;
      RECT 0.190 22.400 176.320 22.540 ;
      RECT 0.190 22.960 176.320 23.100 ;
      RECT 0.190 23.520 176.320 23.660 ;
      RECT 0.190 24.080 176.320 24.220 ;
      RECT 0.190 24.640 176.320 24.780 ;
      RECT 0.190 25.200 176.320 25.340 ;
      RECT 0.190 25.760 176.320 25.900 ;
      RECT 0.190 26.320 176.320 26.460 ;
      RECT 0.190 26.880 176.320 27.020 ;
      RECT 0.190 27.440 176.320 27.580 ;
      RECT 0.190 28.000 176.320 28.140 ;
      RECT 0.190 28.560 176.320 28.700 ;
      RECT 0.190 29.120 176.320 29.260 ;
      RECT 0.190 29.680 176.320 29.820 ;
      RECT 0.190 30.240 176.320 30.380 ;
      RECT 0.190 30.800 176.320 30.940 ;
      RECT 0.190 31.360 176.320 31.500 ;
      RECT 0.190 31.920 176.320 32.060 ;
      RECT 0.190 32.480 176.320 32.620 ;
      RECT 0.190 33.040 176.320 33.180 ;
      RECT 0.190 33.600 176.320 33.740 ;
      RECT 0.190 34.160 176.320 34.300 ;
      RECT 0.190 34.720 176.320 34.860 ;
      RECT 0.190 35.280 176.320 35.420 ;
      RECT 0.190 35.840 176.320 35.980 ;
      RECT 0.190 36.400 176.320 36.540 ;
      RECT 0.190 36.960 176.320 37.100 ;
      RECT 0.190 37.520 176.320 37.660 ;
      RECT 0.190 38.080 176.320 38.220 ;
      RECT 0.190 38.640 176.320 38.780 ;
      RECT 0.190 39.200 176.320 39.340 ;
      RECT 0.190 39.760 176.320 39.900 ;
      RECT 0.190 40.320 176.320 40.460 ;
      RECT 0.190 40.880 176.320 41.020 ;
      RECT 0.190 41.440 176.320 41.580 ;
      RECT 0.190 42.000 176.320 42.140 ;
      RECT 0.190 42.560 176.320 42.700 ;
      RECT 0.190 43.120 176.320 43.260 ;
      RECT 0.190 43.680 176.320 43.820 ;
      RECT 0.190 44.240 176.320 44.380 ;
      RECT 0.190 44.800 176.320 44.940 ;
      RECT 0.190 45.360 176.320 45.500 ;
      RECT 0.190 45.920 176.320 46.060 ;
      RECT 0.190 46.480 176.320 46.620 ;
      RECT 0.190 47.040 176.320 47.180 ;
      RECT 0.190 47.600 176.320 47.740 ;
      RECT 0.190 48.160 176.320 48.300 ;
      RECT 0.190 48.720 176.320 48.860 ;
      RECT 0.190 49.280 176.320 49.420 ;
      RECT 0.190 49.840 176.320 49.980 ;
      RECT 0.190 50.400 176.320 50.540 ;
      RECT 0.190 50.960 176.320 51.100 ;
      RECT 0.190 51.520 176.320 51.660 ;
      RECT 0.190 52.080 176.320 52.220 ;
      RECT 0.190 52.640 176.320 52.780 ;
      RECT 0.190 53.200 176.320 53.340 ;
      RECT 0.190 53.760 176.320 53.900 ;
      RECT 0.190 54.320 176.320 54.460 ;
      RECT 0.190 54.880 176.320 55.020 ;
      RECT 0.190 55.440 176.320 55.580 ;
      RECT 0.190 56.000 176.320 56.140 ;
      RECT 0.190 56.560 176.320 56.700 ;
      RECT 0.190 57.120 176.320 57.260 ;
      RECT 0.190 57.680 176.320 57.820 ;
      RECT 0.190 58.240 176.320 58.380 ;
      RECT 0.190 58.800 176.320 58.940 ;
      RECT 0.190 59.360 176.320 59.500 ;
      RECT 0.190 59.920 176.320 60.060 ;
      RECT 0.190 60.480 176.320 60.620 ;
      RECT 0.190 61.040 176.320 61.180 ;
      RECT 0.190 61.600 176.320 61.740 ;
      RECT 0.190 62.160 176.320 62.300 ;
      RECT 0.190 62.720 176.320 62.860 ;
      RECT 0.190 63.280 176.320 63.420 ;
      RECT 0.190 63.840 176.320 63.980 ;
      RECT 0.190 64.400 176.320 64.540 ;
      RECT 0.190 64.960 176.320 65.100 ;
      RECT 0.190 65.520 176.320 65.660 ;
      RECT 0.190 66.080 176.320 66.220 ;
      RECT 0.190 66.640 176.320 66.780 ;
      RECT 0.190 67.200 176.320 67.340 ;
      RECT 0.190 67.760 176.320 67.900 ;
      RECT 0.190 68.320 176.320 68.460 ;
      RECT 0.190 68.880 176.320 69.020 ;
      RECT 0.190 69.440 176.320 69.580 ;
      RECT 0.190 70.000 176.320 70.140 ;
      RECT 0.190 70.560 176.320 70.700 ;
      RECT 0.190 71.120 176.320 71.260 ;
      RECT 0.190 71.680 176.320 71.820 ;
      RECT 0.190 72.240 176.320 72.380 ;
      RECT 0.190 72.800 176.320 72.940 ;
      RECT 0.190 73.360 176.320 73.500 ;
      RECT 0.190 73.920 176.320 74.060 ;
      RECT 0.190 74.480 176.320 74.620 ;
      RECT 0.190 75.040 176.320 75.180 ;
      RECT 0.190 75.600 176.320 75.740 ;
      RECT 0.190 76.160 176.320 76.300 ;
      RECT 0.190 76.720 176.320 76.860 ;
      RECT 0.190 77.280 176.320 77.420 ;
      RECT 0.190 77.840 176.320 77.980 ;
      RECT 0.190 78.400 176.320 78.540 ;
      RECT 0.190 78.960 176.320 79.100 ;
      RECT 0.190 79.520 176.320 79.660 ;
      RECT 0.190 80.080 176.320 80.220 ;
      RECT 0.190 80.640 176.320 80.780 ;
      RECT 0.190 81.200 176.320 81.340 ;
      RECT 0.190 81.760 176.320 81.900 ;
      RECT 0.190 82.320 176.320 82.460 ;
      RECT 0.190 82.880 176.320 83.020 ;
      RECT 0.190 83.440 176.320 83.580 ;
      RECT 0.190 84.000 176.320 84.140 ;
      RECT 0.190 84.560 176.320 84.700 ;
      RECT 0.190 85.120 176.320 85.260 ;
      RECT 0.190 85.680 176.320 85.820 ;
      RECT 0.190 86.240 176.320 86.380 ;
      RECT 0.190 86.800 176.320 86.940 ;
      RECT 0.190 87.360 176.320 87.500 ;
      RECT 0.190 87.920 176.320 88.060 ;
      RECT 0.190 88.480 176.320 88.620 ;
      RECT 0.190 89.040 176.320 89.180 ;
      RECT 0.190 89.600 176.320 89.740 ;
      RECT 0.190 90.160 176.320 90.300 ;
      RECT 0.190 90.720 176.320 90.860 ;
      RECT 0.190 91.280 176.320 91.420 ;
      RECT 0.190 91.840 176.320 91.980 ;
      RECT 0.190 92.400 176.320 92.540 ;
      RECT 0.190 92.960 176.320 93.100 ;
      RECT 0.190 93.520 176.320 93.660 ;
      RECT 0.190 94.080 176.320 94.220 ;
      RECT 0.190 94.640 176.320 94.780 ;
      RECT 0.190 95.200 176.320 95.340 ;
      RECT 0.190 95.760 176.320 95.900 ;
      RECT 0.190 96.320 176.320 96.460 ;
      RECT 0.190 96.880 176.320 97.020 ;
      RECT 0.190 97.440 176.320 97.580 ;
      RECT 0.190 98.000 176.320 98.140 ;
      RECT 0.190 98.560 176.320 98.700 ;
      RECT 0.190 99.120 176.320 99.260 ;
      RECT 0.190 99.680 176.320 99.820 ;
      RECT 0.190 100.240 176.320 100.380 ;
      RECT 0.190 100.800 176.320 100.940 ;
      RECT 0.190 101.360 176.320 101.500 ;
      RECT 0.190 101.920 176.320 102.060 ;
      RECT 0.190 102.480 176.320 102.620 ;
      RECT 0.190 103.040 176.320 103.180 ;
      RECT 0.190 103.600 176.320 103.740 ;
      RECT 0.190 104.160 176.320 104.300 ;
      RECT 0.190 104.720 176.320 104.860 ;
      RECT 0.190 105.280 176.320 105.420 ;
      RECT 0.190 105.840 176.320 105.980 ;
      RECT 0.190 106.400 176.320 106.540 ;
      RECT 0.190 106.960 176.320 107.100 ;
      RECT 0.190 107.520 176.320 107.660 ;
      RECT 0.190 108.080 176.320 108.220 ;
      RECT 0.190 108.640 176.320 108.780 ;
      RECT 0.190 109.200 176.320 109.340 ;
      RECT 0.190 109.760 176.320 109.900 ;
      RECT 0.190 110.320 176.320 110.460 ;
      RECT 0.190 110.880 176.320 111.020 ;
      RECT 0.190 111.440 176.320 111.580 ;
      RECT 0.190 112.000 176.320 112.140 ;
      RECT 0.190 112.560 176.320 112.700 ;
      RECT 0.190 113.120 176.320 113.260 ;
      RECT 0.190 113.680 176.320 113.820 ;
      RECT 0.190 114.240 176.320 114.380 ;
      RECT 0.190 114.800 176.320 114.940 ;
      RECT 0.190 115.360 176.320 115.500 ;
      RECT 0.190 115.920 176.320 116.060 ;
      RECT 0.190 116.480 176.320 116.620 ;
      RECT 0.190 117.040 176.320 117.180 ;
      RECT 0.190 117.600 176.320 117.740 ;
      RECT 0.190 118.160 176.320 118.300 ;
      RECT 0.190 118.720 176.320 118.860 ;
      RECT 0.190 119.280 176.320 119.420 ;
      RECT 0.190 119.840 176.320 119.980 ;
      RECT 0.190 120.400 176.320 120.540 ;
      RECT 0.190 120.960 176.320 121.100 ;
      RECT 0.190 121.520 176.320 121.660 ;
      RECT 0.190 122.080 176.320 122.220 ;
      RECT 0.190 122.640 176.320 122.780 ;
      RECT 0.190 123.200 176.320 123.340 ;
      RECT 0.190 123.760 176.320 123.900 ;
      RECT 0.190 124.320 176.320 124.460 ;
      RECT 0.190 124.880 176.320 125.020 ;
      RECT 0.190 125.440 176.320 125.580 ;
      RECT 0.190 126.000 176.320 126.140 ;
      RECT 0.190 126.560 176.320 126.700 ;
      RECT 0.190 127.120 176.320 127.260 ;
      RECT 0.190 127.680 176.320 127.820 ;
      RECT 0.190 128.240 176.320 128.380 ;
      RECT 0.190 128.800 176.320 128.940 ;
      RECT 0.190 129.360 176.320 129.500 ;
      RECT 0.190 129.920 176.320 130.060 ;
      RECT 0.190 130.480 176.320 130.620 ;
      RECT 0.190 131.040 176.320 131.180 ;
      RECT 0.190 131.600 176.320 131.740 ;
      RECT 0.190 132.160 176.320 132.300 ;
      RECT 0.190 132.720 176.320 132.860 ;
      RECT 0.190 133.280 176.320 133.420 ;
      RECT 0.190 133.840 176.320 133.980 ;
      RECT 0.190 134.400 176.320 134.540 ;
      RECT 0.190 134.960 176.320 135.100 ;
      RECT 0.190 135.520 176.320 135.660 ;
      RECT 0.190 136.080 176.320 136.220 ;
      RECT 0.190 136.640 176.320 136.780 ;
      RECT 0.190 137.200 176.320 137.340 ;
      RECT 0.190 137.760 176.320 137.900 ;
      RECT 0.190 138.320 176.320 138.460 ;
      RECT 0.190 138.880 176.320 139.020 ;
      RECT 0.190 139.440 176.320 139.580 ;
      RECT 0.190 140.000 176.320 140.140 ;
      RECT 0.190 140.560 176.320 140.700 ;
      RECT 0.190 141.120 176.320 141.260 ;
      RECT 0.190 141.680 176.320 141.820 ;
      RECT 0.190 142.240 176.320 142.380 ;
      RECT 0.190 142.800 176.320 142.940 ;
      RECT 0.190 143.360 176.320 143.500 ;
      RECT 0.190 143.920 176.320 144.060 ;
      RECT 0.190 144.480 176.320 144.620 ;
      RECT 0.190 145.040 176.320 145.180 ;
      RECT 0.190 145.600 176.320 145.740 ;
      RECT 0.190 146.160 176.320 146.300 ;
      RECT 0.190 146.720 176.320 146.860 ;
      RECT 0.190 147.280 176.320 147.420 ;
      RECT 0.190 147.840 176.320 147.980 ;
    END
  END VDD
  PIN VSS
    DIRECTION INOUT ;
    USE GROUND ;
    PORT
      LAYER metal4 ;
      RECT 0.190 0.280 176.320 0.420 ;
      RECT 0.190 0.840 176.320 0.980 ;
      RECT 0.190 1.400 176.320 1.540 ;
      RECT 0.190 1.960 176.320 2.100 ;
      RECT 0.190 2.520 176.320 2.660 ;
      RECT 0.190 3.080 176.320 3.220 ;
      RECT 0.190 3.640 176.320 3.780 ;
      RECT 0.190 4.200 176.320 4.340 ;
      RECT 0.190 4.760 176.320 4.900 ;
      RECT 0.190 5.320 176.320 5.460 ;
      RECT 0.190 5.880 176.320 6.020 ;
      RECT 0.190 6.440 176.320 6.580 ;
      RECT 0.190 7.000 176.320 7.140 ;
      RECT 0.190 7.560 176.320 7.700 ;
      RECT 0.190 8.120 176.320 8.260 ;
      RECT 0.190 8.680 176.320 8.820 ;
      RECT 0.190 9.240 176.320 9.380 ;
      RECT 0.190 9.800 176.320 9.940 ;
      RECT 0.190 10.360 176.320 10.500 ;
      RECT 0.190 10.920 176.320 11.060 ;
      RECT 0.190 11.480 176.320 11.620 ;
      RECT 0.190 12.040 176.320 12.180 ;
      RECT 0.190 12.600 176.320 12.740 ;
      RECT 0.190 13.160 176.320 13.300 ;
      RECT 0.190 13.720 176.320 13.860 ;
      RECT 0.190 14.280 176.320 14.420 ;
      RECT 0.190 14.840 176.320 14.980 ;
      RECT 0.190 15.400 176.320 15.540 ;
      RECT 0.190 15.960 176.320 16.100 ;
      RECT 0.190 16.520 176.320 16.660 ;
      RECT 0.190 17.080 176.320 17.220 ;
      RECT 0.190 17.640 176.320 17.780 ;
      RECT 0.190 18.200 176.320 18.340 ;
      RECT 0.190 18.760 176.320 18.900 ;
      RECT 0.190 19.320 176.320 19.460 ;
      RECT 0.190 19.880 176.320 20.020 ;
      RECT 0.190 20.440 176.320 20.580 ;
      RECT 0.190 21.000 176.320 21.140 ;
      RECT 0.190 21.560 176.320 21.700 ;
      RECT 0.190 22.120 176.320 22.260 ;
      RECT 0.190 22.680 176.320 22.820 ;
      RECT 0.190 23.240 176.320 23.380 ;
      RECT 0.190 23.800 176.320 23.940 ;
      RECT 0.190 24.360 176.320 24.500 ;
      RECT 0.190 24.920 176.320 25.060 ;
      RECT 0.190 25.480 176.320 25.620 ;
      RECT 0.190 26.040 176.320 26.180 ;
      RECT 0.190 26.600 176.320 26.740 ;
      RECT 0.190 27.160 176.320 27.300 ;
      RECT 0.190 27.720 176.320 27.860 ;
      RECT 0.190 28.280 176.320 28.420 ;
      RECT 0.190 28.840 176.320 28.980 ;
      RECT 0.190 29.400 176.320 29.540 ;
      RECT 0.190 29.960 176.320 30.100 ;
      RECT 0.190 30.520 176.320 30.660 ;
      RECT 0.190 31.080 176.320 31.220 ;
      RECT 0.190 31.640 176.320 31.780 ;
      RECT 0.190 32.200 176.320 32.340 ;
      RECT 0.190 32.760 176.320 32.900 ;
      RECT 0.190 33.320 176.320 33.460 ;
      RECT 0.190 33.880 176.320 34.020 ;
      RECT 0.190 34.440 176.320 34.580 ;
      RECT 0.190 35.000 176.320 35.140 ;
      RECT 0.190 35.560 176.320 35.700 ;
      RECT 0.190 36.120 176.320 36.260 ;
      RECT 0.190 36.680 176.320 36.820 ;
      RECT 0.190 37.240 176.320 37.380 ;
      RECT 0.190 37.800 176.320 37.940 ;
      RECT 0.190 38.360 176.320 38.500 ;
      RECT 0.190 38.920 176.320 39.060 ;
      RECT 0.190 39.480 176.320 39.620 ;
      RECT 0.190 40.040 176.320 40.180 ;
      RECT 0.190 40.600 176.320 40.740 ;
      RECT 0.190 41.160 176.320 41.300 ;
      RECT 0.190 41.720 176.320 41.860 ;
      RECT 0.190 42.280 176.320 42.420 ;
      RECT 0.190 42.840 176.320 42.980 ;
      RECT 0.190 43.400 176.320 43.540 ;
      RECT 0.190 43.960 176.320 44.100 ;
      RECT 0.190 44.520 176.320 44.660 ;
      RECT 0.190 45.080 176.320 45.220 ;
      RECT 0.190 45.640 176.320 45.780 ;
      RECT 0.190 46.200 176.320 46.340 ;
      RECT 0.190 46.760 176.320 46.900 ;
      RECT 0.190 47.320 176.320 47.460 ;
      RECT 0.190 47.880 176.320 48.020 ;
      RECT 0.190 48.440 176.320 48.580 ;
      RECT 0.190 49.000 176.320 49.140 ;
      RECT 0.190 49.560 176.320 49.700 ;
      RECT 0.190 50.120 176.320 50.260 ;
      RECT 0.190 50.680 176.320 50.820 ;
      RECT 0.190 51.240 176.320 51.380 ;
      RECT 0.190 51.800 176.320 51.940 ;
      RECT 0.190 52.360 176.320 52.500 ;
      RECT 0.190 52.920 176.320 53.060 ;
      RECT 0.190 53.480 176.320 53.620 ;
      RECT 0.190 54.040 176.320 54.180 ;
      RECT 0.190 54.600 176.320 54.740 ;
      RECT 0.190 55.160 176.320 55.300 ;
      RECT 0.190 55.720 176.320 55.860 ;
      RECT 0.190 56.280 176.320 56.420 ;
      RECT 0.190 56.840 176.320 56.980 ;
      RECT 0.190 57.400 176.320 57.540 ;
      RECT 0.190 57.960 176.320 58.100 ;
      RECT 0.190 58.520 176.320 58.660 ;
      RECT 0.190 59.080 176.320 59.220 ;
      RECT 0.190 59.640 176.320 59.780 ;
      RECT 0.190 60.200 176.320 60.340 ;
      RECT 0.190 60.760 176.320 60.900 ;
      RECT 0.190 61.320 176.320 61.460 ;
      RECT 0.190 61.880 176.320 62.020 ;
      RECT 0.190 62.440 176.320 62.580 ;
      RECT 0.190 63.000 176.320 63.140 ;
      RECT 0.190 63.560 176.320 63.700 ;
      RECT 0.190 64.120 176.320 64.260 ;
      RECT 0.190 64.680 176.320 64.820 ;
      RECT 0.190 65.240 176.320 65.380 ;
      RECT 0.190 65.800 176.320 65.940 ;
      RECT 0.190 66.360 176.320 66.500 ;
      RECT 0.190 66.920 176.320 67.060 ;
      RECT 0.190 67.480 176.320 67.620 ;
      RECT 0.190 68.040 176.320 68.180 ;
      RECT 0.190 68.600 176.320 68.740 ;
      RECT 0.190 69.160 176.320 69.300 ;
      RECT 0.190 69.720 176.320 69.860 ;
      RECT 0.190 70.280 176.320 70.420 ;
      RECT 0.190 70.840 176.320 70.980 ;
      RECT 0.190 71.400 176.320 71.540 ;
      RECT 0.190 71.960 176.320 72.100 ;
      RECT 0.190 72.520 176.320 72.660 ;
      RECT 0.190 73.080 176.320 73.220 ;
      RECT 0.190 73.640 176.320 73.780 ;
      RECT 0.190 74.200 176.320 74.340 ;
      RECT 0.190 74.760 176.320 74.900 ;
      RECT 0.190 75.320 176.320 75.460 ;
      RECT 0.190 75.880 176.320 76.020 ;
      RECT 0.190 76.440 176.320 76.580 ;
      RECT 0.190 77.000 176.320 77.140 ;
      RECT 0.190 77.560 176.320 77.700 ;
      RECT 0.190 78.120 176.320 78.260 ;
      RECT 0.190 78.680 176.320 78.820 ;
      RECT 0.190 79.240 176.320 79.380 ;
      RECT 0.190 79.800 176.320 79.940 ;
      RECT 0.190 80.360 176.320 80.500 ;
      RECT 0.190 80.920 176.320 81.060 ;
      RECT 0.190 81.480 176.320 81.620 ;
      RECT 0.190 82.040 176.320 82.180 ;
      RECT 0.190 82.600 176.320 82.740 ;
      RECT 0.190 83.160 176.320 83.300 ;
      RECT 0.190 83.720 176.320 83.860 ;
      RECT 0.190 84.280 176.320 84.420 ;
      RECT 0.190 84.840 176.320 84.980 ;
      RECT 0.190 85.400 176.320 85.540 ;
      RECT 0.190 85.960 176.320 86.100 ;
      RECT 0.190 86.520 176.320 86.660 ;
      RECT 0.190 87.080 176.320 87.220 ;
      RECT 0.190 87.640 176.320 87.780 ;
      RECT 0.190 88.200 176.320 88.340 ;
      RECT 0.190 88.760 176.320 88.900 ;
      RECT 0.190 89.320 176.320 89.460 ;
      RECT 0.190 89.880 176.320 90.020 ;
      RECT 0.190 90.440 176.320 90.580 ;
      RECT 0.190 91.000 176.320 91.140 ;
      RECT 0.190 91.560 176.320 91.700 ;
      RECT 0.190 92.120 176.320 92.260 ;
      RECT 0.190 92.680 176.320 92.820 ;
      RECT 0.190 93.240 176.320 93.380 ;
      RECT 0.190 93.800 176.320 93.940 ;
      RECT 0.190 94.360 176.320 94.500 ;
      RECT 0.190 94.920 176.320 95.060 ;
      RECT 0.190 95.480 176.320 95.620 ;
      RECT 0.190 96.040 176.320 96.180 ;
      RECT 0.190 96.600 176.320 96.740 ;
      RECT 0.190 97.160 176.320 97.300 ;
      RECT 0.190 97.720 176.320 97.860 ;
      RECT 0.190 98.280 176.320 98.420 ;
      RECT 0.190 98.840 176.320 98.980 ;
      RECT 0.190 99.400 176.320 99.540 ;
      RECT 0.190 99.960 176.320 100.100 ;
      RECT 0.190 100.520 176.320 100.660 ;
      RECT 0.190 101.080 176.320 101.220 ;
      RECT 0.190 101.640 176.320 101.780 ;
      RECT 0.190 102.200 176.320 102.340 ;
      RECT 0.190 102.760 176.320 102.900 ;
      RECT 0.190 103.320 176.320 103.460 ;
      RECT 0.190 103.880 176.320 104.020 ;
      RECT 0.190 104.440 176.320 104.580 ;
      RECT 0.190 105.000 176.320 105.140 ;
      RECT 0.190 105.560 176.320 105.700 ;
      RECT 0.190 106.120 176.320 106.260 ;
      RECT 0.190 106.680 176.320 106.820 ;
      RECT 0.190 107.240 176.320 107.380 ;
      RECT 0.190 107.800 176.320 107.940 ;
      RECT 0.190 108.360 176.320 108.500 ;
      RECT 0.190 108.920 176.320 109.060 ;
      RECT 0.190 109.480 176.320 109.620 ;
      RECT 0.190 110.040 176.320 110.180 ;
      RECT 0.190 110.600 176.320 110.740 ;
      RECT 0.190 111.160 176.320 111.300 ;
      RECT 0.190 111.720 176.320 111.860 ;
      RECT 0.190 112.280 176.320 112.420 ;
      RECT 0.190 112.840 176.320 112.980 ;
      RECT 0.190 113.400 176.320 113.540 ;
      RECT 0.190 113.960 176.320 114.100 ;
      RECT 0.190 114.520 176.320 114.660 ;
      RECT 0.190 115.080 176.320 115.220 ;
      RECT 0.190 115.640 176.320 115.780 ;
      RECT 0.190 116.200 176.320 116.340 ;
      RECT 0.190 116.760 176.320 116.900 ;
      RECT 0.190 117.320 176.320 117.460 ;
      RECT 0.190 117.880 176.320 118.020 ;
      RECT 0.190 118.440 176.320 118.580 ;
      RECT 0.190 119.000 176.320 119.140 ;
      RECT 0.190 119.560 176.320 119.700 ;
      RECT 0.190 120.120 176.320 120.260 ;
      RECT 0.190 120.680 176.320 120.820 ;
      RECT 0.190 121.240 176.320 121.380 ;
      RECT 0.190 121.800 176.320 121.940 ;
      RECT 0.190 122.360 176.320 122.500 ;
      RECT 0.190 122.920 176.320 123.060 ;
      RECT 0.190 123.480 176.320 123.620 ;
      RECT 0.190 124.040 176.320 124.180 ;
      RECT 0.190 124.600 176.320 124.740 ;
      RECT 0.190 125.160 176.320 125.300 ;
      RECT 0.190 125.720 176.320 125.860 ;
      RECT 0.190 126.280 176.320 126.420 ;
      RECT 0.190 126.840 176.320 126.980 ;
      RECT 0.190 127.400 176.320 127.540 ;
      RECT 0.190 127.960 176.320 128.100 ;
      RECT 0.190 128.520 176.320 128.660 ;
      RECT 0.190 129.080 176.320 129.220 ;
      RECT 0.190 129.640 176.320 129.780 ;
      RECT 0.190 130.200 176.320 130.340 ;
      RECT 0.190 130.760 176.320 130.900 ;
      RECT 0.190 131.320 176.320 131.460 ;
      RECT 0.190 131.880 176.320 132.020 ;
      RECT 0.190 132.440 176.320 132.580 ;
      RECT 0.190 133.000 176.320 133.140 ;
      RECT 0.190 133.560 176.320 133.700 ;
      RECT 0.190 134.120 176.320 134.260 ;
      RECT 0.190 134.680 176.320 134.820 ;
      RECT 0.190 135.240 176.320 135.380 ;
      RECT 0.190 135.800 176.320 135.940 ;
      RECT 0.190 136.360 176.320 136.500 ;
      RECT 0.190 136.920 176.320 137.060 ;
      RECT 0.190 137.480 176.320 137.620 ;
      RECT 0.190 138.040 176.320 138.180 ;
      RECT 0.190 138.600 176.320 138.740 ;
      RECT 0.190 139.160 176.320 139.300 ;
      RECT 0.190 139.720 176.320 139.860 ;
      RECT 0.190 140.280 176.320 140.420 ;
      RECT 0.190 140.840 176.320 140.980 ;
      RECT 0.190 141.400 176.320 141.540 ;
      RECT 0.190 141.960 176.320 142.100 ;
      RECT 0.190 142.520 176.320 142.660 ;
      RECT 0.190 143.080 176.320 143.220 ;
      RECT 0.190 143.640 176.320 143.780 ;
      RECT 0.190 144.200 176.320 144.340 ;
      RECT 0.190 144.760 176.320 144.900 ;
      RECT 0.190 145.320 176.320 145.460 ;
      RECT 0.190 145.880 176.320 146.020 ;
      RECT 0.190 146.440 176.320 146.580 ;
      RECT 0.190 147.000 176.320 147.140 ;
      RECT 0.190 147.560 176.320 147.700 ;
      RECT 0.190 148.120 176.320 148.260 ;
    END
  END VSS
  OBS
    LAYER metal1 ;
      RECT 0.000 0.000 176.510 148.400 ;
    LAYER metal2 ;
      RECT 0.000 0.000 176.510 148.400 ;
    LAYER metal3 ;
      RECT 0.000 0.000 176.510 148.400 ;
  END
END fakeram_256x16_1r1w
END LIBRARY
